VERSION 5.8 ;
BUSBITCHARS "[]" ;
DIVIDERCHAR "/" ;
UNITS
    DATABASE MICRONS 1000 ;
END UNITS

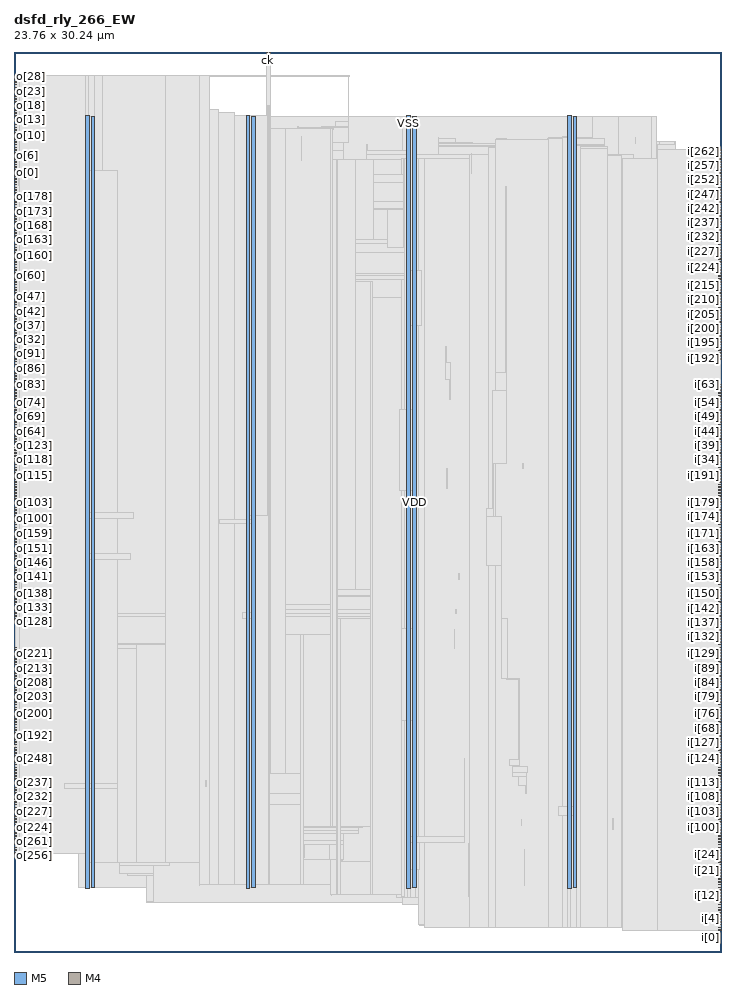
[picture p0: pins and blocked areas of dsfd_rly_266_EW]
MACRO dsfd_rly_266_EW
  FOREIGN dsfd_rly_266_EW 0 0 ;
  CLASS BLOCK ;
  SIZE 23.76 BY 30.24 ;
  PIN ck
    DIRECTION INPUT ;
    USE SIGNAL ;
    PORT
      LAYER M5 ;
        RECT  8.496 30.156 8.52 30.24 ;
    END
  END ck
  PIN i[0]
    DIRECTION INPUT ;
    USE SIGNAL ;
    PORT
      LAYER M4 ;
        RECT  23.676 0.72 23.76 0.744 ;
    END
  END i[0]
  PIN i[100]
    DIRECTION INPUT ;
    USE SIGNAL ;
    PORT
      LAYER M4 ;
        RECT  23.676 4.176 23.76 4.2 ;
    END
  END i[100]
  PIN i[101]
    DIRECTION INPUT ;
    USE SIGNAL ;
    PORT
      LAYER M4 ;
        RECT  23.676 4.272 23.76 4.296 ;
    END
  END i[101]
  PIN i[102]
    DIRECTION INPUT ;
    USE SIGNAL ;
    PORT
      LAYER M4 ;
        RECT  23.676 4.368 23.76 4.392 ;
    END
  END i[102]
  PIN i[103]
    DIRECTION INPUT ;
    USE SIGNAL ;
    PORT
      LAYER M4 ;
        RECT  23.676 4.464 23.76 4.488 ;
    END
  END i[103]
  PIN i[104]
    DIRECTION INPUT ;
    USE SIGNAL ;
    PORT
      LAYER M4 ;
        RECT  23.676 4.56 23.76 4.584 ;
    END
  END i[104]
  PIN i[105]
    DIRECTION INPUT ;
    USE SIGNAL ;
    PORT
      LAYER M4 ;
        RECT  23.676 4.656 23.76 4.68 ;
    END
  END i[105]
  PIN i[106]
    DIRECTION INPUT ;
    USE SIGNAL ;
    PORT
      LAYER M4 ;
        RECT  23.676 4.752 23.76 4.776 ;
    END
  END i[106]
  PIN i[107]
    DIRECTION INPUT ;
    USE SIGNAL ;
    PORT
      LAYER M4 ;
        RECT  23.676 4.848 23.76 4.872 ;
    END
  END i[107]
  PIN i[108]
    DIRECTION INPUT ;
    USE SIGNAL ;
    PORT
      LAYER M4 ;
        RECT  23.676 4.944 23.76 4.968 ;
    END
  END i[108]
  PIN i[109]
    DIRECTION INPUT ;
    USE SIGNAL ;
    PORT
      LAYER M4 ;
        RECT  23.676 5.04 23.76 5.064 ;
    END
  END i[109]
  PIN i[10]
    DIRECTION INPUT ;
    USE SIGNAL ;
    PORT
      LAYER M4 ;
        RECT  23.676 1.68 23.76 1.704 ;
    END
  END i[10]
  PIN i[110]
    DIRECTION INPUT ;
    USE SIGNAL ;
    PORT
      LAYER M4 ;
        RECT  23.676 5.136 23.76 5.16 ;
    END
  END i[110]
  PIN i[111]
    DIRECTION INPUT ;
    USE SIGNAL ;
    PORT
      LAYER M4 ;
        RECT  23.676 5.232 23.76 5.256 ;
    END
  END i[111]
  PIN i[112]
    DIRECTION INPUT ;
    USE SIGNAL ;
    PORT
      LAYER M4 ;
        RECT  23.676 5.328 23.76 5.352 ;
    END
  END i[112]
  PIN i[113]
    DIRECTION INPUT ;
    USE SIGNAL ;
    PORT
      LAYER M4 ;
        RECT  23.676 5.424 23.76 5.448 ;
    END
  END i[113]
  PIN i[114]
    DIRECTION INPUT ;
    USE SIGNAL ;
    PORT
      LAYER M4 ;
        RECT  23.676 5.52 23.76 5.544 ;
    END
  END i[114]
  PIN i[115]
    DIRECTION INPUT ;
    USE SIGNAL ;
    PORT
      LAYER M4 ;
        RECT  23.676 5.616 23.76 5.64 ;
    END
  END i[115]
  PIN i[116]
    DIRECTION INPUT ;
    USE SIGNAL ;
    PORT
      LAYER M4 ;
        RECT  23.676 5.712 23.76 5.736 ;
    END
  END i[116]
  PIN i[117]
    DIRECTION INPUT ;
    USE SIGNAL ;
    PORT
      LAYER M4 ;
        RECT  23.676 5.808 23.76 5.832 ;
    END
  END i[117]
  PIN i[118]
    DIRECTION INPUT ;
    USE SIGNAL ;
    PORT
      LAYER M4 ;
        RECT  23.676 5.904 23.76 5.928 ;
    END
  END i[118]
  PIN i[119]
    DIRECTION INPUT ;
    USE SIGNAL ;
    PORT
      LAYER M4 ;
        RECT  23.676 6 23.76 6.024 ;
    END
  END i[119]
  PIN i[11]
    DIRECTION INPUT ;
    USE SIGNAL ;
    PORT
      LAYER M4 ;
        RECT  23.676 1.776 23.76 1.8 ;
    END
  END i[11]
  PIN i[120]
    DIRECTION INPUT ;
    USE SIGNAL ;
    PORT
      LAYER M4 ;
        RECT  23.676 6.096 23.76 6.12 ;
    END
  END i[120]
  PIN i[121]
    DIRECTION INPUT ;
    USE SIGNAL ;
    PORT
      LAYER M4 ;
        RECT  23.676 6.192 23.76 6.216 ;
    END
  END i[121]
  PIN i[122]
    DIRECTION INPUT ;
    USE SIGNAL ;
    PORT
      LAYER M4 ;
        RECT  23.676 6.288 23.76 6.312 ;
    END
  END i[122]
  PIN i[123]
    DIRECTION INPUT ;
    USE SIGNAL ;
    PORT
      LAYER M4 ;
        RECT  23.676 6.384 23.76 6.408 ;
    END
  END i[123]
  PIN i[124]
    DIRECTION INPUT ;
    USE SIGNAL ;
    PORT
      LAYER M4 ;
        RECT  23.676 6.48 23.76 6.504 ;
    END
  END i[124]
  PIN i[125]
    DIRECTION INPUT ;
    USE SIGNAL ;
    PORT
      LAYER M4 ;
        RECT  23.676 6.576 23.76 6.6 ;
    END
  END i[125]
  PIN i[126]
    DIRECTION INPUT ;
    USE SIGNAL ;
    PORT
      LAYER M4 ;
        RECT  23.676 6.672 23.76 6.696 ;
    END
  END i[126]
  PIN i[127]
    DIRECTION INPUT ;
    USE SIGNAL ;
    PORT
      LAYER M4 ;
        RECT  23.676 6.768 23.76 6.792 ;
    END
  END i[127]
  PIN i[128]
    DIRECTION INPUT ;
    USE SIGNAL ;
    PORT
      LAYER M4 ;
        RECT  23.676 9.936 23.76 9.96 ;
    END
  END i[128]
  PIN i[129]
    DIRECTION INPUT ;
    USE SIGNAL ;
    PORT
      LAYER M4 ;
        RECT  23.676 10.032 23.76 10.056 ;
    END
  END i[129]
  PIN i[12]
    DIRECTION INPUT ;
    USE SIGNAL ;
    PORT
      LAYER M4 ;
        RECT  23.676 1.872 23.76 1.896 ;
    END
  END i[12]
  PIN i[130]
    DIRECTION INPUT ;
    USE SIGNAL ;
    PORT
      LAYER M4 ;
        RECT  23.676 10.128 23.76 10.152 ;
    END
  END i[130]
  PIN i[131]
    DIRECTION INPUT ;
    USE SIGNAL ;
    PORT
      LAYER M4 ;
        RECT  23.676 10.224 23.76 10.248 ;
    END
  END i[131]
  PIN i[132]
    DIRECTION INPUT ;
    USE SIGNAL ;
    PORT
      LAYER M4 ;
        RECT  23.676 10.32 23.76 10.344 ;
    END
  END i[132]
  PIN i[133]
    DIRECTION INPUT ;
    USE SIGNAL ;
    PORT
      LAYER M4 ;
        RECT  23.676 10.416 23.76 10.44 ;
    END
  END i[133]
  PIN i[134]
    DIRECTION INPUT ;
    USE SIGNAL ;
    PORT
      LAYER M4 ;
        RECT  23.676 10.512 23.76 10.536 ;
    END
  END i[134]
  PIN i[135]
    DIRECTION INPUT ;
    USE SIGNAL ;
    PORT
      LAYER M4 ;
        RECT  23.676 10.608 23.76 10.632 ;
    END
  END i[135]
  PIN i[136]
    DIRECTION INPUT ;
    USE SIGNAL ;
    PORT
      LAYER M4 ;
        RECT  23.676 10.704 23.76 10.728 ;
    END
  END i[136]
  PIN i[137]
    DIRECTION INPUT ;
    USE SIGNAL ;
    PORT
      LAYER M4 ;
        RECT  23.676 10.8 23.76 10.824 ;
    END
  END i[137]
  PIN i[138]
    DIRECTION INPUT ;
    USE SIGNAL ;
    PORT
      LAYER M4 ;
        RECT  23.676 10.896 23.76 10.92 ;
    END
  END i[138]
  PIN i[139]
    DIRECTION INPUT ;
    USE SIGNAL ;
    PORT
      LAYER M4 ;
        RECT  23.676 10.992 23.76 11.016 ;
    END
  END i[139]
  PIN i[13]
    DIRECTION INPUT ;
    USE SIGNAL ;
    PORT
      LAYER M4 ;
        RECT  23.676 1.968 23.76 1.992 ;
    END
  END i[13]
  PIN i[140]
    DIRECTION INPUT ;
    USE SIGNAL ;
    PORT
      LAYER M4 ;
        RECT  23.676 11.088 23.76 11.112 ;
    END
  END i[140]
  PIN i[141]
    DIRECTION INPUT ;
    USE SIGNAL ;
    PORT
      LAYER M4 ;
        RECT  23.676 11.184 23.76 11.208 ;
    END
  END i[141]
  PIN i[142]
    DIRECTION INPUT ;
    USE SIGNAL ;
    PORT
      LAYER M4 ;
        RECT  23.676 11.28 23.76 11.304 ;
    END
  END i[142]
  PIN i[143]
    DIRECTION INPUT ;
    USE SIGNAL ;
    PORT
      LAYER M4 ;
        RECT  23.676 11.376 23.76 11.4 ;
    END
  END i[143]
  PIN i[144]
    DIRECTION INPUT ;
    USE SIGNAL ;
    PORT
      LAYER M4 ;
        RECT  23.676 11.472 23.76 11.496 ;
    END
  END i[144]
  PIN i[145]
    DIRECTION INPUT ;
    USE SIGNAL ;
    PORT
      LAYER M4 ;
        RECT  23.676 11.568 23.76 11.592 ;
    END
  END i[145]
  PIN i[146]
    DIRECTION INPUT ;
    USE SIGNAL ;
    PORT
      LAYER M4 ;
        RECT  23.676 11.664 23.76 11.688 ;
    END
  END i[146]
  PIN i[147]
    DIRECTION INPUT ;
    USE SIGNAL ;
    PORT
      LAYER M4 ;
        RECT  23.676 11.76 23.76 11.784 ;
    END
  END i[147]
  PIN i[148]
    DIRECTION INPUT ;
    USE SIGNAL ;
    PORT
      LAYER M4 ;
        RECT  23.676 11.856 23.76 11.88 ;
    END
  END i[148]
  PIN i[149]
    DIRECTION INPUT ;
    USE SIGNAL ;
    PORT
      LAYER M4 ;
        RECT  23.676 11.952 23.76 11.976 ;
    END
  END i[149]
  PIN i[14]
    DIRECTION INPUT ;
    USE SIGNAL ;
    PORT
      LAYER M4 ;
        RECT  23.676 2.064 23.76 2.088 ;
    END
  END i[14]
  PIN i[150]
    DIRECTION INPUT ;
    USE SIGNAL ;
    PORT
      LAYER M4 ;
        RECT  23.676 12.048 23.76 12.072 ;
    END
  END i[150]
  PIN i[151]
    DIRECTION INPUT ;
    USE SIGNAL ;
    PORT
      LAYER M4 ;
        RECT  23.676 12.144 23.76 12.168 ;
    END
  END i[151]
  PIN i[152]
    DIRECTION INPUT ;
    USE SIGNAL ;
    PORT
      LAYER M4 ;
        RECT  23.676 12.24 23.76 12.264 ;
    END
  END i[152]
  PIN i[153]
    DIRECTION INPUT ;
    USE SIGNAL ;
    PORT
      LAYER M4 ;
        RECT  23.676 12.336 23.76 12.36 ;
    END
  END i[153]
  PIN i[154]
    DIRECTION INPUT ;
    USE SIGNAL ;
    PORT
      LAYER M4 ;
        RECT  23.676 12.432 23.76 12.456 ;
    END
  END i[154]
  PIN i[155]
    DIRECTION INPUT ;
    USE SIGNAL ;
    PORT
      LAYER M4 ;
        RECT  23.676 12.528 23.76 12.552 ;
    END
  END i[155]
  PIN i[156]
    DIRECTION INPUT ;
    USE SIGNAL ;
    PORT
      LAYER M4 ;
        RECT  23.676 12.624 23.76 12.648 ;
    END
  END i[156]
  PIN i[157]
    DIRECTION INPUT ;
    USE SIGNAL ;
    PORT
      LAYER M4 ;
        RECT  23.676 12.72 23.76 12.744 ;
    END
  END i[157]
  PIN i[158]
    DIRECTION INPUT ;
    USE SIGNAL ;
    PORT
      LAYER M4 ;
        RECT  23.676 12.816 23.76 12.84 ;
    END
  END i[158]
  PIN i[159]
    DIRECTION INPUT ;
    USE SIGNAL ;
    PORT
      LAYER M4 ;
        RECT  23.676 12.912 23.76 12.936 ;
    END
  END i[159]
  PIN i[15]
    DIRECTION INPUT ;
    USE SIGNAL ;
    PORT
      LAYER M4 ;
        RECT  23.676 2.16 23.76 2.184 ;
    END
  END i[15]
  PIN i[160]
    DIRECTION INPUT ;
    USE SIGNAL ;
    PORT
      LAYER M4 ;
        RECT  23.676 13.008 23.76 13.032 ;
    END
  END i[160]
  PIN i[161]
    DIRECTION INPUT ;
    USE SIGNAL ;
    PORT
      LAYER M4 ;
        RECT  23.676 13.104 23.76 13.128 ;
    END
  END i[161]
  PIN i[162]
    DIRECTION INPUT ;
    USE SIGNAL ;
    PORT
      LAYER M4 ;
        RECT  23.676 13.2 23.76 13.224 ;
    END
  END i[162]
  PIN i[163]
    DIRECTION INPUT ;
    USE SIGNAL ;
    PORT
      LAYER M4 ;
        RECT  23.676 13.296 23.76 13.32 ;
    END
  END i[163]
  PIN i[164]
    DIRECTION INPUT ;
    USE SIGNAL ;
    PORT
      LAYER M4 ;
        RECT  23.676 13.392 23.76 13.416 ;
    END
  END i[164]
  PIN i[165]
    DIRECTION INPUT ;
    USE SIGNAL ;
    PORT
      LAYER M4 ;
        RECT  23.676 13.488 23.76 13.512 ;
    END
  END i[165]
  PIN i[166]
    DIRECTION INPUT ;
    USE SIGNAL ;
    PORT
      LAYER M4 ;
        RECT  23.676 13.584 23.76 13.608 ;
    END
  END i[166]
  PIN i[167]
    DIRECTION INPUT ;
    USE SIGNAL ;
    PORT
      LAYER M4 ;
        RECT  23.676 13.68 23.76 13.704 ;
    END
  END i[167]
  PIN i[168]
    DIRECTION INPUT ;
    USE SIGNAL ;
    PORT
      LAYER M4 ;
        RECT  23.676 13.776 23.76 13.8 ;
    END
  END i[168]
  PIN i[169]
    DIRECTION INPUT ;
    USE SIGNAL ;
    PORT
      LAYER M4 ;
        RECT  23.676 13.872 23.76 13.896 ;
    END
  END i[169]
  PIN i[16]
    DIRECTION INPUT ;
    USE SIGNAL ;
    PORT
      LAYER M4 ;
        RECT  23.676 2.256 23.76 2.28 ;
    END
  END i[16]
  PIN i[170]
    DIRECTION INPUT ;
    USE SIGNAL ;
    PORT
      LAYER M4 ;
        RECT  23.676 13.968 23.76 13.992 ;
    END
  END i[170]
  PIN i[171]
    DIRECTION INPUT ;
    USE SIGNAL ;
    PORT
      LAYER M4 ;
        RECT  23.676 14.064 23.76 14.088 ;
    END
  END i[171]
  PIN i[172]
    DIRECTION INPUT ;
    USE SIGNAL ;
    PORT
      LAYER M4 ;
        RECT  23.676 14.16 23.76 14.184 ;
    END
  END i[172]
  PIN i[173]
    DIRECTION INPUT ;
    USE SIGNAL ;
    PORT
      LAYER M4 ;
        RECT  23.676 14.256 23.76 14.28 ;
    END
  END i[173]
  PIN i[174]
    DIRECTION INPUT ;
    USE SIGNAL ;
    PORT
      LAYER M4 ;
        RECT  23.676 14.352 23.76 14.376 ;
    END
  END i[174]
  PIN i[175]
    DIRECTION INPUT ;
    USE SIGNAL ;
    PORT
      LAYER M4 ;
        RECT  23.676 14.448 23.76 14.472 ;
    END
  END i[175]
  PIN i[176]
    DIRECTION INPUT ;
    USE SIGNAL ;
    PORT
      LAYER M4 ;
        RECT  23.676 14.544 23.76 14.568 ;
    END
  END i[176]
  PIN i[177]
    DIRECTION INPUT ;
    USE SIGNAL ;
    PORT
      LAYER M4 ;
        RECT  23.676 14.64 23.76 14.664 ;
    END
  END i[177]
  PIN i[178]
    DIRECTION INPUT ;
    USE SIGNAL ;
    PORT
      LAYER M4 ;
        RECT  23.676 14.736 23.76 14.76 ;
    END
  END i[178]
  PIN i[179]
    DIRECTION INPUT ;
    USE SIGNAL ;
    PORT
      LAYER M4 ;
        RECT  23.676 14.832 23.76 14.856 ;
    END
  END i[179]
  PIN i[17]
    DIRECTION INPUT ;
    USE SIGNAL ;
    PORT
      LAYER M4 ;
        RECT  23.676 2.352 23.76 2.376 ;
    END
  END i[17]
  PIN i[180]
    DIRECTION INPUT ;
    USE SIGNAL ;
    PORT
      LAYER M4 ;
        RECT  23.676 14.928 23.76 14.952 ;
    END
  END i[180]
  PIN i[181]
    DIRECTION INPUT ;
    USE SIGNAL ;
    PORT
      LAYER M4 ;
        RECT  23.676 15.024 23.76 15.048 ;
    END
  END i[181]
  PIN i[182]
    DIRECTION INPUT ;
    USE SIGNAL ;
    PORT
      LAYER M4 ;
        RECT  23.676 15.12 23.76 15.144 ;
    END
  END i[182]
  PIN i[183]
    DIRECTION INPUT ;
    USE SIGNAL ;
    PORT
      LAYER M4 ;
        RECT  23.676 15.216 23.76 15.24 ;
    END
  END i[183]
  PIN i[184]
    DIRECTION INPUT ;
    USE SIGNAL ;
    PORT
      LAYER M4 ;
        RECT  23.676 15.312 23.76 15.336 ;
    END
  END i[184]
  PIN i[185]
    DIRECTION INPUT ;
    USE SIGNAL ;
    PORT
      LAYER M4 ;
        RECT  23.676 15.408 23.76 15.432 ;
    END
  END i[185]
  PIN i[186]
    DIRECTION INPUT ;
    USE SIGNAL ;
    PORT
      LAYER M4 ;
        RECT  23.676 15.504 23.76 15.528 ;
    END
  END i[186]
  PIN i[187]
    DIRECTION INPUT ;
    USE SIGNAL ;
    PORT
      LAYER M4 ;
        RECT  23.676 15.6 23.76 15.624 ;
    END
  END i[187]
  PIN i[188]
    DIRECTION INPUT ;
    USE SIGNAL ;
    PORT
      LAYER M4 ;
        RECT  23.676 15.696 23.76 15.72 ;
    END
  END i[188]
  PIN i[189]
    DIRECTION INPUT ;
    USE SIGNAL ;
    PORT
      LAYER M4 ;
        RECT  23.676 15.792 23.76 15.816 ;
    END
  END i[189]
  PIN i[18]
    DIRECTION INPUT ;
    USE SIGNAL ;
    PORT
      LAYER M4 ;
        RECT  23.676 2.448 23.76 2.472 ;
    END
  END i[18]
  PIN i[190]
    DIRECTION INPUT ;
    USE SIGNAL ;
    PORT
      LAYER M4 ;
        RECT  23.676 15.888 23.76 15.912 ;
    END
  END i[190]
  PIN i[191]
    DIRECTION INPUT ;
    USE SIGNAL ;
    PORT
      LAYER M4 ;
        RECT  23.676 15.984 23.76 16.008 ;
    END
  END i[191]
  PIN i[192]
    DIRECTION INPUT ;
    USE SIGNAL ;
    PORT
      LAYER M4 ;
        RECT  23.676 19.92 23.76 19.944 ;
    END
  END i[192]
  PIN i[193]
    DIRECTION INPUT ;
    USE SIGNAL ;
    PORT
      LAYER M4 ;
        RECT  23.676 20.016 23.76 20.04 ;
    END
  END i[193]
  PIN i[194]
    DIRECTION INPUT ;
    USE SIGNAL ;
    PORT
      LAYER M4 ;
        RECT  23.676 20.112 23.76 20.136 ;
    END
  END i[194]
  PIN i[195]
    DIRECTION INPUT ;
    USE SIGNAL ;
    PORT
      LAYER M4 ;
        RECT  23.676 20.208 23.76 20.232 ;
    END
  END i[195]
  PIN i[196]
    DIRECTION INPUT ;
    USE SIGNAL ;
    PORT
      LAYER M4 ;
        RECT  23.676 20.304 23.76 20.328 ;
    END
  END i[196]
  PIN i[197]
    DIRECTION INPUT ;
    USE SIGNAL ;
    PORT
      LAYER M4 ;
        RECT  23.676 20.4 23.76 20.424 ;
    END
  END i[197]
  PIN i[198]
    DIRECTION INPUT ;
    USE SIGNAL ;
    PORT
      LAYER M4 ;
        RECT  23.676 20.496 23.76 20.52 ;
    END
  END i[198]
  PIN i[199]
    DIRECTION INPUT ;
    USE SIGNAL ;
    PORT
      LAYER M4 ;
        RECT  23.676 20.592 23.76 20.616 ;
    END
  END i[199]
  PIN i[19]
    DIRECTION INPUT ;
    USE SIGNAL ;
    PORT
      LAYER M4 ;
        RECT  23.676 2.544 23.76 2.568 ;
    END
  END i[19]
  PIN i[1]
    DIRECTION INPUT ;
    USE SIGNAL ;
    PORT
      LAYER M4 ;
        RECT  23.676 0.816 23.76 0.84 ;
    END
  END i[1]
  PIN i[200]
    DIRECTION INPUT ;
    USE SIGNAL ;
    PORT
      LAYER M4 ;
        RECT  23.676 20.688 23.76 20.712 ;
    END
  END i[200]
  PIN i[201]
    DIRECTION INPUT ;
    USE SIGNAL ;
    PORT
      LAYER M4 ;
        RECT  23.676 20.784 23.76 20.808 ;
    END
  END i[201]
  PIN i[202]
    DIRECTION INPUT ;
    USE SIGNAL ;
    PORT
      LAYER M4 ;
        RECT  23.676 20.88 23.76 20.904 ;
    END
  END i[202]
  PIN i[203]
    DIRECTION INPUT ;
    USE SIGNAL ;
    PORT
      LAYER M4 ;
        RECT  23.676 20.976 23.76 21 ;
    END
  END i[203]
  PIN i[204]
    DIRECTION INPUT ;
    USE SIGNAL ;
    PORT
      LAYER M4 ;
        RECT  23.676 21.072 23.76 21.096 ;
    END
  END i[204]
  PIN i[205]
    DIRECTION INPUT ;
    USE SIGNAL ;
    PORT
      LAYER M4 ;
        RECT  23.676 21.168 23.76 21.192 ;
    END
  END i[205]
  PIN i[206]
    DIRECTION INPUT ;
    USE SIGNAL ;
    PORT
      LAYER M4 ;
        RECT  23.676 21.264 23.76 21.288 ;
    END
  END i[206]
  PIN i[207]
    DIRECTION INPUT ;
    USE SIGNAL ;
    PORT
      LAYER M4 ;
        RECT  23.676 21.36 23.76 21.384 ;
    END
  END i[207]
  PIN i[208]
    DIRECTION INPUT ;
    USE SIGNAL ;
    PORT
      LAYER M4 ;
        RECT  23.676 21.456 23.76 21.48 ;
    END
  END i[208]
  PIN i[209]
    DIRECTION INPUT ;
    USE SIGNAL ;
    PORT
      LAYER M4 ;
        RECT  23.676 21.552 23.76 21.576 ;
    END
  END i[209]
  PIN i[20]
    DIRECTION INPUT ;
    USE SIGNAL ;
    PORT
      LAYER M4 ;
        RECT  23.676 2.64 23.76 2.664 ;
    END
  END i[20]
  PIN i[210]
    DIRECTION INPUT ;
    USE SIGNAL ;
    PORT
      LAYER M4 ;
        RECT  23.676 21.648 23.76 21.672 ;
    END
  END i[210]
  PIN i[211]
    DIRECTION INPUT ;
    USE SIGNAL ;
    PORT
      LAYER M4 ;
        RECT  23.676 21.744 23.76 21.768 ;
    END
  END i[211]
  PIN i[212]
    DIRECTION INPUT ;
    USE SIGNAL ;
    PORT
      LAYER M4 ;
        RECT  23.676 21.84 23.76 21.864 ;
    END
  END i[212]
  PIN i[213]
    DIRECTION INPUT ;
    USE SIGNAL ;
    PORT
      LAYER M4 ;
        RECT  23.676 21.936 23.76 21.96 ;
    END
  END i[213]
  PIN i[214]
    DIRECTION INPUT ;
    USE SIGNAL ;
    PORT
      LAYER M4 ;
        RECT  23.676 22.032 23.76 22.056 ;
    END
  END i[214]
  PIN i[215]
    DIRECTION INPUT ;
    USE SIGNAL ;
    PORT
      LAYER M4 ;
        RECT  23.676 22.128 23.76 22.152 ;
    END
  END i[215]
  PIN i[216]
    DIRECTION INPUT ;
    USE SIGNAL ;
    PORT
      LAYER M4 ;
        RECT  23.676 22.224 23.76 22.248 ;
    END
  END i[216]
  PIN i[217]
    DIRECTION INPUT ;
    USE SIGNAL ;
    PORT
      LAYER M4 ;
        RECT  23.676 22.32 23.76 22.344 ;
    END
  END i[217]
  PIN i[218]
    DIRECTION INPUT ;
    USE SIGNAL ;
    PORT
      LAYER M4 ;
        RECT  23.676 22.416 23.76 22.44 ;
    END
  END i[218]
  PIN i[219]
    DIRECTION INPUT ;
    USE SIGNAL ;
    PORT
      LAYER M4 ;
        RECT  23.676 22.512 23.76 22.536 ;
    END
  END i[219]
  PIN i[21]
    DIRECTION INPUT ;
    USE SIGNAL ;
    PORT
      LAYER M4 ;
        RECT  23.676 2.736 23.76 2.76 ;
    END
  END i[21]
  PIN i[220]
    DIRECTION INPUT ;
    USE SIGNAL ;
    PORT
      LAYER M4 ;
        RECT  23.676 22.608 23.76 22.632 ;
    END
  END i[220]
  PIN i[221]
    DIRECTION INPUT ;
    USE SIGNAL ;
    PORT
      LAYER M4 ;
        RECT  23.676 22.704 23.76 22.728 ;
    END
  END i[221]
  PIN i[222]
    DIRECTION INPUT ;
    USE SIGNAL ;
    PORT
      LAYER M4 ;
        RECT  23.676 22.8 23.76 22.824 ;
    END
  END i[222]
  PIN i[223]
    DIRECTION INPUT ;
    USE SIGNAL ;
    PORT
      LAYER M4 ;
        RECT  23.676 22.896 23.76 22.92 ;
    END
  END i[223]
  PIN i[224]
    DIRECTION INPUT ;
    USE SIGNAL ;
    PORT
      LAYER M4 ;
        RECT  23.676 22.992 23.76 23.016 ;
    END
  END i[224]
  PIN i[225]
    DIRECTION INPUT ;
    USE SIGNAL ;
    PORT
      LAYER M4 ;
        RECT  23.676 23.088 23.76 23.112 ;
    END
  END i[225]
  PIN i[226]
    DIRECTION INPUT ;
    USE SIGNAL ;
    PORT
      LAYER M4 ;
        RECT  23.676 23.184 23.76 23.208 ;
    END
  END i[226]
  PIN i[227]
    DIRECTION INPUT ;
    USE SIGNAL ;
    PORT
      LAYER M4 ;
        RECT  23.676 23.28 23.76 23.304 ;
    END
  END i[227]
  PIN i[228]
    DIRECTION INPUT ;
    USE SIGNAL ;
    PORT
      LAYER M4 ;
        RECT  23.676 23.376 23.76 23.4 ;
    END
  END i[228]
  PIN i[229]
    DIRECTION INPUT ;
    USE SIGNAL ;
    PORT
      LAYER M4 ;
        RECT  23.676 23.472 23.76 23.496 ;
    END
  END i[229]
  PIN i[22]
    DIRECTION INPUT ;
    USE SIGNAL ;
    PORT
      LAYER M4 ;
        RECT  23.676 2.832 23.76 2.856 ;
    END
  END i[22]
  PIN i[230]
    DIRECTION INPUT ;
    USE SIGNAL ;
    PORT
      LAYER M4 ;
        RECT  23.676 23.568 23.76 23.592 ;
    END
  END i[230]
  PIN i[231]
    DIRECTION INPUT ;
    USE SIGNAL ;
    PORT
      LAYER M4 ;
        RECT  23.676 23.664 23.76 23.688 ;
    END
  END i[231]
  PIN i[232]
    DIRECTION INPUT ;
    USE SIGNAL ;
    PORT
      LAYER M4 ;
        RECT  23.676 23.76 23.76 23.784 ;
    END
  END i[232]
  PIN i[233]
    DIRECTION INPUT ;
    USE SIGNAL ;
    PORT
      LAYER M4 ;
        RECT  23.676 23.856 23.76 23.88 ;
    END
  END i[233]
  PIN i[234]
    DIRECTION INPUT ;
    USE SIGNAL ;
    PORT
      LAYER M4 ;
        RECT  23.676 23.952 23.76 23.976 ;
    END
  END i[234]
  PIN i[235]
    DIRECTION INPUT ;
    USE SIGNAL ;
    PORT
      LAYER M4 ;
        RECT  23.676 24.048 23.76 24.072 ;
    END
  END i[235]
  PIN i[236]
    DIRECTION INPUT ;
    USE SIGNAL ;
    PORT
      LAYER M4 ;
        RECT  23.676 24.144 23.76 24.168 ;
    END
  END i[236]
  PIN i[237]
    DIRECTION INPUT ;
    USE SIGNAL ;
    PORT
      LAYER M4 ;
        RECT  23.676 24.24 23.76 24.264 ;
    END
  END i[237]
  PIN i[238]
    DIRECTION INPUT ;
    USE SIGNAL ;
    PORT
      LAYER M4 ;
        RECT  23.676 24.336 23.76 24.36 ;
    END
  END i[238]
  PIN i[239]
    DIRECTION INPUT ;
    USE SIGNAL ;
    PORT
      LAYER M4 ;
        RECT  23.676 24.432 23.76 24.456 ;
    END
  END i[239]
  PIN i[23]
    DIRECTION INPUT ;
    USE SIGNAL ;
    PORT
      LAYER M4 ;
        RECT  23.676 2.928 23.76 2.952 ;
    END
  END i[23]
  PIN i[240]
    DIRECTION INPUT ;
    USE SIGNAL ;
    PORT
      LAYER M4 ;
        RECT  23.676 24.528 23.76 24.552 ;
    END
  END i[240]
  PIN i[241]
    DIRECTION INPUT ;
    USE SIGNAL ;
    PORT
      LAYER M4 ;
        RECT  23.676 24.624 23.76 24.648 ;
    END
  END i[241]
  PIN i[242]
    DIRECTION INPUT ;
    USE SIGNAL ;
    PORT
      LAYER M4 ;
        RECT  23.676 24.72 23.76 24.744 ;
    END
  END i[242]
  PIN i[243]
    DIRECTION INPUT ;
    USE SIGNAL ;
    PORT
      LAYER M4 ;
        RECT  23.676 24.816 23.76 24.84 ;
    END
  END i[243]
  PIN i[244]
    DIRECTION INPUT ;
    USE SIGNAL ;
    PORT
      LAYER M4 ;
        RECT  23.676 24.912 23.76 24.936 ;
    END
  END i[244]
  PIN i[245]
    DIRECTION INPUT ;
    USE SIGNAL ;
    PORT
      LAYER M4 ;
        RECT  23.676 25.008 23.76 25.032 ;
    END
  END i[245]
  PIN i[246]
    DIRECTION INPUT ;
    USE SIGNAL ;
    PORT
      LAYER M4 ;
        RECT  23.676 25.104 23.76 25.128 ;
    END
  END i[246]
  PIN i[247]
    DIRECTION INPUT ;
    USE SIGNAL ;
    PORT
      LAYER M4 ;
        RECT  23.676 25.2 23.76 25.224 ;
    END
  END i[247]
  PIN i[248]
    DIRECTION INPUT ;
    USE SIGNAL ;
    PORT
      LAYER M4 ;
        RECT  23.676 25.296 23.76 25.32 ;
    END
  END i[248]
  PIN i[249]
    DIRECTION INPUT ;
    USE SIGNAL ;
    PORT
      LAYER M4 ;
        RECT  23.676 25.392 23.76 25.416 ;
    END
  END i[249]
  PIN i[24]
    DIRECTION INPUT ;
    USE SIGNAL ;
    PORT
      LAYER M4 ;
        RECT  23.676 3.024 23.76 3.048 ;
    END
  END i[24]
  PIN i[250]
    DIRECTION INPUT ;
    USE SIGNAL ;
    PORT
      LAYER M4 ;
        RECT  23.676 25.488 23.76 25.512 ;
    END
  END i[250]
  PIN i[251]
    DIRECTION INPUT ;
    USE SIGNAL ;
    PORT
      LAYER M4 ;
        RECT  23.676 25.584 23.76 25.608 ;
    END
  END i[251]
  PIN i[252]
    DIRECTION INPUT ;
    USE SIGNAL ;
    PORT
      LAYER M4 ;
        RECT  23.676 25.68 23.76 25.704 ;
    END
  END i[252]
  PIN i[253]
    DIRECTION INPUT ;
    USE SIGNAL ;
    PORT
      LAYER M4 ;
        RECT  23.676 25.776 23.76 25.8 ;
    END
  END i[253]
  PIN i[254]
    DIRECTION INPUT ;
    USE SIGNAL ;
    PORT
      LAYER M4 ;
        RECT  23.676 25.872 23.76 25.896 ;
    END
  END i[254]
  PIN i[255]
    DIRECTION INPUT ;
    USE SIGNAL ;
    PORT
      LAYER M4 ;
        RECT  23.676 25.968 23.76 25.992 ;
    END
  END i[255]
  PIN i[256]
    DIRECTION INPUT ;
    USE SIGNAL ;
    PORT
      LAYER M4 ;
        RECT  23.676 26.064 23.76 26.088 ;
    END
  END i[256]
  PIN i[257]
    DIRECTION INPUT ;
    USE SIGNAL ;
    PORT
      LAYER M4 ;
        RECT  23.676 26.16 23.76 26.184 ;
    END
  END i[257]
  PIN i[258]
    DIRECTION INPUT ;
    USE SIGNAL ;
    PORT
      LAYER M4 ;
        RECT  23.676 26.256 23.76 26.28 ;
    END
  END i[258]
  PIN i[259]
    DIRECTION INPUT ;
    USE SIGNAL ;
    PORT
      LAYER M4 ;
        RECT  23.676 26.352 23.76 26.376 ;
    END
  END i[259]
  PIN i[25]
    DIRECTION INPUT ;
    USE SIGNAL ;
    PORT
      LAYER M4 ;
        RECT  23.676 3.12 23.76 3.144 ;
    END
  END i[25]
  PIN i[260]
    DIRECTION INPUT ;
    USE SIGNAL ;
    PORT
      LAYER M4 ;
        RECT  23.676 26.448 23.76 26.472 ;
    END
  END i[260]
  PIN i[261]
    DIRECTION INPUT ;
    USE SIGNAL ;
    PORT
      LAYER M4 ;
        RECT  23.676 26.544 23.76 26.568 ;
    END
  END i[261]
  PIN i[262]
    DIRECTION INPUT ;
    USE SIGNAL ;
    PORT
      LAYER M4 ;
        RECT  23.676 26.64 23.76 26.664 ;
    END
  END i[262]
  PIN i[263]
    DIRECTION INPUT ;
    USE SIGNAL ;
    PORT
      LAYER M4 ;
        RECT  23.676 26.736 23.76 26.76 ;
    END
  END i[263]
  PIN i[264]
    DIRECTION INPUT ;
    USE SIGNAL ;
    PORT
      LAYER M4 ;
        RECT  23.676 26.832 23.76 26.856 ;
    END
  END i[264]
  PIN i[265]
    DIRECTION INPUT ;
    USE SIGNAL ;
    PORT
      LAYER M4 ;
        RECT  23.676 26.928 23.76 26.952 ;
    END
  END i[265]
  PIN i[26]
    DIRECTION INPUT ;
    USE SIGNAL ;
    PORT
      LAYER M4 ;
        RECT  23.676 3.216 23.76 3.24 ;
    END
  END i[26]
  PIN i[27]
    DIRECTION INPUT ;
    USE SIGNAL ;
    PORT
      LAYER M4 ;
        RECT  23.676 3.312 23.76 3.336 ;
    END
  END i[27]
  PIN i[28]
    DIRECTION INPUT ;
    USE SIGNAL ;
    PORT
      LAYER M4 ;
        RECT  23.676 3.408 23.76 3.432 ;
    END
  END i[28]
  PIN i[29]
    DIRECTION INPUT ;
    USE SIGNAL ;
    PORT
      LAYER M4 ;
        RECT  23.676 3.504 23.76 3.528 ;
    END
  END i[29]
  PIN i[2]
    DIRECTION INPUT ;
    USE SIGNAL ;
    PORT
      LAYER M4 ;
        RECT  23.676 0.912 23.76 0.936 ;
    END
  END i[2]
  PIN i[30]
    DIRECTION INPUT ;
    USE SIGNAL ;
    PORT
      LAYER M4 ;
        RECT  23.676 3.6 23.76 3.624 ;
    END
  END i[30]
  PIN i[31]
    DIRECTION INPUT ;
    USE SIGNAL ;
    PORT
      LAYER M4 ;
        RECT  23.676 3.696 23.76 3.72 ;
    END
  END i[31]
  PIN i[32]
    DIRECTION INPUT ;
    USE SIGNAL ;
    PORT
      LAYER M4 ;
        RECT  23.676 16.08 23.76 16.104 ;
    END
  END i[32]
  PIN i[33]
    DIRECTION INPUT ;
    USE SIGNAL ;
    PORT
      LAYER M4 ;
        RECT  23.676 16.176 23.76 16.2 ;
    END
  END i[33]
  PIN i[34]
    DIRECTION INPUT ;
    USE SIGNAL ;
    PORT
      LAYER M4 ;
        RECT  23.676 16.272 23.76 16.296 ;
    END
  END i[34]
  PIN i[35]
    DIRECTION INPUT ;
    USE SIGNAL ;
    PORT
      LAYER M4 ;
        RECT  23.676 16.368 23.76 16.392 ;
    END
  END i[35]
  PIN i[36]
    DIRECTION INPUT ;
    USE SIGNAL ;
    PORT
      LAYER M4 ;
        RECT  23.676 16.464 23.76 16.488 ;
    END
  END i[36]
  PIN i[37]
    DIRECTION INPUT ;
    USE SIGNAL ;
    PORT
      LAYER M4 ;
        RECT  23.676 16.56 23.76 16.584 ;
    END
  END i[37]
  PIN i[38]
    DIRECTION INPUT ;
    USE SIGNAL ;
    PORT
      LAYER M4 ;
        RECT  23.676 16.656 23.76 16.68 ;
    END
  END i[38]
  PIN i[39]
    DIRECTION INPUT ;
    USE SIGNAL ;
    PORT
      LAYER M4 ;
        RECT  23.676 16.752 23.76 16.776 ;
    END
  END i[39]
  PIN i[3]
    DIRECTION INPUT ;
    USE SIGNAL ;
    PORT
      LAYER M4 ;
        RECT  23.676 1.008 23.76 1.032 ;
    END
  END i[3]
  PIN i[40]
    DIRECTION INPUT ;
    USE SIGNAL ;
    PORT
      LAYER M4 ;
        RECT  23.676 16.848 23.76 16.872 ;
    END
  END i[40]
  PIN i[41]
    DIRECTION INPUT ;
    USE SIGNAL ;
    PORT
      LAYER M4 ;
        RECT  23.676 16.944 23.76 16.968 ;
    END
  END i[41]
  PIN i[42]
    DIRECTION INPUT ;
    USE SIGNAL ;
    PORT
      LAYER M4 ;
        RECT  23.676 17.04 23.76 17.064 ;
    END
  END i[42]
  PIN i[43]
    DIRECTION INPUT ;
    USE SIGNAL ;
    PORT
      LAYER M4 ;
        RECT  23.676 17.136 23.76 17.16 ;
    END
  END i[43]
  PIN i[44]
    DIRECTION INPUT ;
    USE SIGNAL ;
    PORT
      LAYER M4 ;
        RECT  23.676 17.232 23.76 17.256 ;
    END
  END i[44]
  PIN i[45]
    DIRECTION INPUT ;
    USE SIGNAL ;
    PORT
      LAYER M4 ;
        RECT  23.676 17.328 23.76 17.352 ;
    END
  END i[45]
  PIN i[46]
    DIRECTION INPUT ;
    USE SIGNAL ;
    PORT
      LAYER M4 ;
        RECT  23.676 17.424 23.76 17.448 ;
    END
  END i[46]
  PIN i[47]
    DIRECTION INPUT ;
    USE SIGNAL ;
    PORT
      LAYER M4 ;
        RECT  23.676 17.52 23.76 17.544 ;
    END
  END i[47]
  PIN i[48]
    DIRECTION INPUT ;
    USE SIGNAL ;
    PORT
      LAYER M4 ;
        RECT  23.676 17.616 23.76 17.64 ;
    END
  END i[48]
  PIN i[49]
    DIRECTION INPUT ;
    USE SIGNAL ;
    PORT
      LAYER M4 ;
        RECT  23.676 17.712 23.76 17.736 ;
    END
  END i[49]
  PIN i[4]
    DIRECTION INPUT ;
    USE SIGNAL ;
    PORT
      LAYER M4 ;
        RECT  23.676 1.104 23.76 1.128 ;
    END
  END i[4]
  PIN i[50]
    DIRECTION INPUT ;
    USE SIGNAL ;
    PORT
      LAYER M4 ;
        RECT  23.676 17.808 23.76 17.832 ;
    END
  END i[50]
  PIN i[51]
    DIRECTION INPUT ;
    USE SIGNAL ;
    PORT
      LAYER M4 ;
        RECT  23.676 17.904 23.76 17.928 ;
    END
  END i[51]
  PIN i[52]
    DIRECTION INPUT ;
    USE SIGNAL ;
    PORT
      LAYER M4 ;
        RECT  23.676 18 23.76 18.024 ;
    END
  END i[52]
  PIN i[53]
    DIRECTION INPUT ;
    USE SIGNAL ;
    PORT
      LAYER M4 ;
        RECT  23.676 18.096 23.76 18.12 ;
    END
  END i[53]
  PIN i[54]
    DIRECTION INPUT ;
    USE SIGNAL ;
    PORT
      LAYER M4 ;
        RECT  23.676 18.192 23.76 18.216 ;
    END
  END i[54]
  PIN i[55]
    DIRECTION INPUT ;
    USE SIGNAL ;
    PORT
      LAYER M4 ;
        RECT  23.676 18.288 23.76 18.312 ;
    END
  END i[55]
  PIN i[56]
    DIRECTION INPUT ;
    USE SIGNAL ;
    PORT
      LAYER M4 ;
        RECT  23.676 18.384 23.76 18.408 ;
    END
  END i[56]
  PIN i[57]
    DIRECTION INPUT ;
    USE SIGNAL ;
    PORT
      LAYER M4 ;
        RECT  23.676 18.48 23.76 18.504 ;
    END
  END i[57]
  PIN i[58]
    DIRECTION INPUT ;
    USE SIGNAL ;
    PORT
      LAYER M4 ;
        RECT  23.676 18.576 23.76 18.6 ;
    END
  END i[58]
  PIN i[59]
    DIRECTION INPUT ;
    USE SIGNAL ;
    PORT
      LAYER M4 ;
        RECT  23.676 18.672 23.76 18.696 ;
    END
  END i[59]
  PIN i[5]
    DIRECTION INPUT ;
    USE SIGNAL ;
    PORT
      LAYER M4 ;
        RECT  23.676 1.2 23.76 1.224 ;
    END
  END i[5]
  PIN i[60]
    DIRECTION INPUT ;
    USE SIGNAL ;
    PORT
      LAYER M4 ;
        RECT  23.676 18.768 23.76 18.792 ;
    END
  END i[60]
  PIN i[61]
    DIRECTION INPUT ;
    USE SIGNAL ;
    PORT
      LAYER M4 ;
        RECT  23.676 18.864 23.76 18.888 ;
    END
  END i[61]
  PIN i[62]
    DIRECTION INPUT ;
    USE SIGNAL ;
    PORT
      LAYER M4 ;
        RECT  23.676 18.96 23.76 18.984 ;
    END
  END i[62]
  PIN i[63]
    DIRECTION INPUT ;
    USE SIGNAL ;
    PORT
      LAYER M4 ;
        RECT  23.676 19.056 23.76 19.08 ;
    END
  END i[63]
  PIN i[64]
    DIRECTION INPUT ;
    USE SIGNAL ;
    PORT
      LAYER M4 ;
        RECT  23.676 6.864 23.76 6.888 ;
    END
  END i[64]
  PIN i[65]
    DIRECTION INPUT ;
    USE SIGNAL ;
    PORT
      LAYER M4 ;
        RECT  23.676 6.96 23.76 6.984 ;
    END
  END i[65]
  PIN i[66]
    DIRECTION INPUT ;
    USE SIGNAL ;
    PORT
      LAYER M4 ;
        RECT  23.676 7.056 23.76 7.08 ;
    END
  END i[66]
  PIN i[67]
    DIRECTION INPUT ;
    USE SIGNAL ;
    PORT
      LAYER M4 ;
        RECT  23.676 7.152 23.76 7.176 ;
    END
  END i[67]
  PIN i[68]
    DIRECTION INPUT ;
    USE SIGNAL ;
    PORT
      LAYER M4 ;
        RECT  23.676 7.248 23.76 7.272 ;
    END
  END i[68]
  PIN i[69]
    DIRECTION INPUT ;
    USE SIGNAL ;
    PORT
      LAYER M4 ;
        RECT  23.676 7.344 23.76 7.368 ;
    END
  END i[69]
  PIN i[6]
    DIRECTION INPUT ;
    USE SIGNAL ;
    PORT
      LAYER M4 ;
        RECT  23.676 1.296 23.76 1.32 ;
    END
  END i[6]
  PIN i[70]
    DIRECTION INPUT ;
    USE SIGNAL ;
    PORT
      LAYER M4 ;
        RECT  23.676 7.44 23.76 7.464 ;
    END
  END i[70]
  PIN i[71]
    DIRECTION INPUT ;
    USE SIGNAL ;
    PORT
      LAYER M4 ;
        RECT  23.676 7.536 23.76 7.56 ;
    END
  END i[71]
  PIN i[72]
    DIRECTION INPUT ;
    USE SIGNAL ;
    PORT
      LAYER M4 ;
        RECT  23.676 7.632 23.76 7.656 ;
    END
  END i[72]
  PIN i[73]
    DIRECTION INPUT ;
    USE SIGNAL ;
    PORT
      LAYER M4 ;
        RECT  23.676 7.728 23.76 7.752 ;
    END
  END i[73]
  PIN i[74]
    DIRECTION INPUT ;
    USE SIGNAL ;
    PORT
      LAYER M4 ;
        RECT  23.676 7.824 23.76 7.848 ;
    END
  END i[74]
  PIN i[75]
    DIRECTION INPUT ;
    USE SIGNAL ;
    PORT
      LAYER M4 ;
        RECT  23.676 7.92 23.76 7.944 ;
    END
  END i[75]
  PIN i[76]
    DIRECTION INPUT ;
    USE SIGNAL ;
    PORT
      LAYER M4 ;
        RECT  23.676 8.016 23.76 8.04 ;
    END
  END i[76]
  PIN i[77]
    DIRECTION INPUT ;
    USE SIGNAL ;
    PORT
      LAYER M4 ;
        RECT  23.676 8.112 23.76 8.136 ;
    END
  END i[77]
  PIN i[78]
    DIRECTION INPUT ;
    USE SIGNAL ;
    PORT
      LAYER M4 ;
        RECT  23.676 8.208 23.76 8.232 ;
    END
  END i[78]
  PIN i[79]
    DIRECTION INPUT ;
    USE SIGNAL ;
    PORT
      LAYER M4 ;
        RECT  23.676 8.304 23.76 8.328 ;
    END
  END i[79]
  PIN i[7]
    DIRECTION INPUT ;
    USE SIGNAL ;
    PORT
      LAYER M4 ;
        RECT  23.676 1.392 23.76 1.416 ;
    END
  END i[7]
  PIN i[80]
    DIRECTION INPUT ;
    USE SIGNAL ;
    PORT
      LAYER M4 ;
        RECT  23.676 8.4 23.76 8.424 ;
    END
  END i[80]
  PIN i[81]
    DIRECTION INPUT ;
    USE SIGNAL ;
    PORT
      LAYER M4 ;
        RECT  23.676 8.496 23.76 8.52 ;
    END
  END i[81]
  PIN i[82]
    DIRECTION INPUT ;
    USE SIGNAL ;
    PORT
      LAYER M4 ;
        RECT  23.676 8.592 23.76 8.616 ;
    END
  END i[82]
  PIN i[83]
    DIRECTION INPUT ;
    USE SIGNAL ;
    PORT
      LAYER M4 ;
        RECT  23.676 8.688 23.76 8.712 ;
    END
  END i[83]
  PIN i[84]
    DIRECTION INPUT ;
    USE SIGNAL ;
    PORT
      LAYER M4 ;
        RECT  23.676 8.784 23.76 8.808 ;
    END
  END i[84]
  PIN i[85]
    DIRECTION INPUT ;
    USE SIGNAL ;
    PORT
      LAYER M4 ;
        RECT  23.676 8.88 23.76 8.904 ;
    END
  END i[85]
  PIN i[86]
    DIRECTION INPUT ;
    USE SIGNAL ;
    PORT
      LAYER M4 ;
        RECT  23.676 8.976 23.76 9 ;
    END
  END i[86]
  PIN i[87]
    DIRECTION INPUT ;
    USE SIGNAL ;
    PORT
      LAYER M4 ;
        RECT  23.676 9.072 23.76 9.096 ;
    END
  END i[87]
  PIN i[88]
    DIRECTION INPUT ;
    USE SIGNAL ;
    PORT
      LAYER M4 ;
        RECT  23.676 9.168 23.76 9.192 ;
    END
  END i[88]
  PIN i[89]
    DIRECTION INPUT ;
    USE SIGNAL ;
    PORT
      LAYER M4 ;
        RECT  23.676 9.264 23.76 9.288 ;
    END
  END i[89]
  PIN i[8]
    DIRECTION INPUT ;
    USE SIGNAL ;
    PORT
      LAYER M4 ;
        RECT  23.676 1.488 23.76 1.512 ;
    END
  END i[8]
  PIN i[90]
    DIRECTION INPUT ;
    USE SIGNAL ;
    PORT
      LAYER M4 ;
        RECT  23.676 9.36 23.76 9.384 ;
    END
  END i[90]
  PIN i[91]
    DIRECTION INPUT ;
    USE SIGNAL ;
    PORT
      LAYER M4 ;
        RECT  23.676 9.456 23.76 9.48 ;
    END
  END i[91]
  PIN i[92]
    DIRECTION INPUT ;
    USE SIGNAL ;
    PORT
      LAYER M4 ;
        RECT  23.676 9.552 23.76 9.576 ;
    END
  END i[92]
  PIN i[93]
    DIRECTION INPUT ;
    USE SIGNAL ;
    PORT
      LAYER M4 ;
        RECT  23.676 9.648 23.76 9.672 ;
    END
  END i[93]
  PIN i[94]
    DIRECTION INPUT ;
    USE SIGNAL ;
    PORT
      LAYER M4 ;
        RECT  23.676 9.744 23.76 9.768 ;
    END
  END i[94]
  PIN i[95]
    DIRECTION INPUT ;
    USE SIGNAL ;
    PORT
      LAYER M4 ;
        RECT  23.676 9.84 23.76 9.864 ;
    END
  END i[95]
  PIN i[96]
    DIRECTION INPUT ;
    USE SIGNAL ;
    PORT
      LAYER M4 ;
        RECT  23.676 3.792 23.76 3.816 ;
    END
  END i[96]
  PIN i[97]
    DIRECTION INPUT ;
    USE SIGNAL ;
    PORT
      LAYER M4 ;
        RECT  23.676 3.888 23.76 3.912 ;
    END
  END i[97]
  PIN i[98]
    DIRECTION INPUT ;
    USE SIGNAL ;
    PORT
      LAYER M4 ;
        RECT  23.676 3.984 23.76 4.008 ;
    END
  END i[98]
  PIN i[99]
    DIRECTION INPUT ;
    USE SIGNAL ;
    PORT
      LAYER M4 ;
        RECT  23.676 4.08 23.76 4.104 ;
    END
  END i[99]
  PIN i[9]
    DIRECTION INPUT ;
    USE SIGNAL ;
    PORT
      LAYER M4 ;
        RECT  23.676 1.584 23.76 1.608 ;
    END
  END i[9]
  PIN o[0]
    DIRECTION OUTPUT ;
    USE SIGNAL ;
    PORT
      LAYER M4 ;
        RECT  0 26.448 0.084 26.472 ;
    END
  END o[0]
  PIN o[100]
    DIRECTION OUTPUT ;
    USE SIGNAL ;
    PORT
      LAYER M4 ;
        RECT  0 14.544 0.084 14.568 ;
    END
  END o[100]
  PIN o[101]
    DIRECTION OUTPUT ;
    USE SIGNAL ;
    PORT
      LAYER M4 ;
        RECT  0 14.64 0.084 14.664 ;
    END
  END o[101]
  PIN o[102]
    DIRECTION OUTPUT ;
    USE SIGNAL ;
    PORT
      LAYER M4 ;
        RECT  0 14.736 0.084 14.76 ;
    END
  END o[102]
  PIN o[103]
    DIRECTION OUTPUT ;
    USE SIGNAL ;
    PORT
      LAYER M4 ;
        RECT  0 14.832 0.084 14.856 ;
    END
  END o[103]
  PIN o[104]
    DIRECTION OUTPUT ;
    USE SIGNAL ;
    PORT
      LAYER M4 ;
        RECT  0 14.928 0.084 14.952 ;
    END
  END o[104]
  PIN o[105]
    DIRECTION OUTPUT ;
    USE SIGNAL ;
    PORT
      LAYER M4 ;
        RECT  0 15.024 0.084 15.048 ;
    END
  END o[105]
  PIN o[106]
    DIRECTION OUTPUT ;
    USE SIGNAL ;
    PORT
      LAYER M4 ;
        RECT  0 15.12 0.084 15.144 ;
    END
  END o[106]
  PIN o[107]
    DIRECTION OUTPUT ;
    USE SIGNAL ;
    PORT
      LAYER M4 ;
        RECT  0 15.216 0.084 15.24 ;
    END
  END o[107]
  PIN o[108]
    DIRECTION OUTPUT ;
    USE SIGNAL ;
    PORT
      LAYER M4 ;
        RECT  0 15.312 0.084 15.336 ;
    END
  END o[108]
  PIN o[109]
    DIRECTION OUTPUT ;
    USE SIGNAL ;
    PORT
      LAYER M4 ;
        RECT  0 15.408 0.084 15.432 ;
    END
  END o[109]
  PIN o[10]
    DIRECTION OUTPUT ;
    USE SIGNAL ;
    PORT
      LAYER M4 ;
        RECT  0 27.408 0.084 27.432 ;
    END
  END o[10]
  PIN o[110]
    DIRECTION OUTPUT ;
    USE SIGNAL ;
    PORT
      LAYER M4 ;
        RECT  0 15.504 0.084 15.528 ;
    END
  END o[110]
  PIN o[111]
    DIRECTION OUTPUT ;
    USE SIGNAL ;
    PORT
      LAYER M4 ;
        RECT  0 15.6 0.084 15.624 ;
    END
  END o[111]
  PIN o[112]
    DIRECTION OUTPUT ;
    USE SIGNAL ;
    PORT
      LAYER M4 ;
        RECT  0 15.696 0.084 15.72 ;
    END
  END o[112]
  PIN o[113]
    DIRECTION OUTPUT ;
    USE SIGNAL ;
    PORT
      LAYER M4 ;
        RECT  0 15.792 0.084 15.816 ;
    END
  END o[113]
  PIN o[114]
    DIRECTION OUTPUT ;
    USE SIGNAL ;
    PORT
      LAYER M4 ;
        RECT  0 15.888 0.084 15.912 ;
    END
  END o[114]
  PIN o[115]
    DIRECTION OUTPUT ;
    USE SIGNAL ;
    PORT
      LAYER M4 ;
        RECT  0 15.984 0.084 16.008 ;
    END
  END o[115]
  PIN o[116]
    DIRECTION OUTPUT ;
    USE SIGNAL ;
    PORT
      LAYER M4 ;
        RECT  0 16.08 0.084 16.104 ;
    END
  END o[116]
  PIN o[117]
    DIRECTION OUTPUT ;
    USE SIGNAL ;
    PORT
      LAYER M4 ;
        RECT  0 16.176 0.084 16.2 ;
    END
  END o[117]
  PIN o[118]
    DIRECTION OUTPUT ;
    USE SIGNAL ;
    PORT
      LAYER M4 ;
        RECT  0 16.272 0.084 16.296 ;
    END
  END o[118]
  PIN o[119]
    DIRECTION OUTPUT ;
    USE SIGNAL ;
    PORT
      LAYER M4 ;
        RECT  0 16.368 0.084 16.392 ;
    END
  END o[119]
  PIN o[11]
    DIRECTION OUTPUT ;
    USE SIGNAL ;
    PORT
      LAYER M4 ;
        RECT  0 27.504 0.084 27.528 ;
    END
  END o[11]
  PIN o[120]
    DIRECTION OUTPUT ;
    USE SIGNAL ;
    PORT
      LAYER M4 ;
        RECT  0 16.464 0.084 16.488 ;
    END
  END o[120]
  PIN o[121]
    DIRECTION OUTPUT ;
    USE SIGNAL ;
    PORT
      LAYER M4 ;
        RECT  0 16.56 0.084 16.584 ;
    END
  END o[121]
  PIN o[122]
    DIRECTION OUTPUT ;
    USE SIGNAL ;
    PORT
      LAYER M4 ;
        RECT  0 16.656 0.084 16.68 ;
    END
  END o[122]
  PIN o[123]
    DIRECTION OUTPUT ;
    USE SIGNAL ;
    PORT
      LAYER M4 ;
        RECT  0 16.752 0.084 16.776 ;
    END
  END o[123]
  PIN o[124]
    DIRECTION OUTPUT ;
    USE SIGNAL ;
    PORT
      LAYER M4 ;
        RECT  0 16.848 0.084 16.872 ;
    END
  END o[124]
  PIN o[125]
    DIRECTION OUTPUT ;
    USE SIGNAL ;
    PORT
      LAYER M4 ;
        RECT  0 16.944 0.084 16.968 ;
    END
  END o[125]
  PIN o[126]
    DIRECTION OUTPUT ;
    USE SIGNAL ;
    PORT
      LAYER M4 ;
        RECT  0 17.04 0.084 17.064 ;
    END
  END o[126]
  PIN o[127]
    DIRECTION OUTPUT ;
    USE SIGNAL ;
    PORT
      LAYER M4 ;
        RECT  0 17.136 0.084 17.16 ;
    END
  END o[127]
  PIN o[128]
    DIRECTION OUTPUT ;
    USE SIGNAL ;
    PORT
      LAYER M4 ;
        RECT  0 11.088 0.084 11.112 ;
    END
  END o[128]
  PIN o[129]
    DIRECTION OUTPUT ;
    USE SIGNAL ;
    PORT
      LAYER M4 ;
        RECT  0 11.184 0.084 11.208 ;
    END
  END o[129]
  PIN o[12]
    DIRECTION OUTPUT ;
    USE SIGNAL ;
    PORT
      LAYER M4 ;
        RECT  0 27.6 0.084 27.624 ;
    END
  END o[12]
  PIN o[130]
    DIRECTION OUTPUT ;
    USE SIGNAL ;
    PORT
      LAYER M4 ;
        RECT  0 11.28 0.084 11.304 ;
    END
  END o[130]
  PIN o[131]
    DIRECTION OUTPUT ;
    USE SIGNAL ;
    PORT
      LAYER M4 ;
        RECT  0 11.376 0.084 11.4 ;
    END
  END o[131]
  PIN o[132]
    DIRECTION OUTPUT ;
    USE SIGNAL ;
    PORT
      LAYER M4 ;
        RECT  0 11.472 0.084 11.496 ;
    END
  END o[132]
  PIN o[133]
    DIRECTION OUTPUT ;
    USE SIGNAL ;
    PORT
      LAYER M4 ;
        RECT  0 11.568 0.084 11.592 ;
    END
  END o[133]
  PIN o[134]
    DIRECTION OUTPUT ;
    USE SIGNAL ;
    PORT
      LAYER M4 ;
        RECT  0 11.664 0.084 11.688 ;
    END
  END o[134]
  PIN o[135]
    DIRECTION OUTPUT ;
    USE SIGNAL ;
    PORT
      LAYER M4 ;
        RECT  0 11.76 0.084 11.784 ;
    END
  END o[135]
  PIN o[136]
    DIRECTION OUTPUT ;
    USE SIGNAL ;
    PORT
      LAYER M4 ;
        RECT  0 11.856 0.084 11.88 ;
    END
  END o[136]
  PIN o[137]
    DIRECTION OUTPUT ;
    USE SIGNAL ;
    PORT
      LAYER M4 ;
        RECT  0 11.952 0.084 11.976 ;
    END
  END o[137]
  PIN o[138]
    DIRECTION OUTPUT ;
    USE SIGNAL ;
    PORT
      LAYER M4 ;
        RECT  0 12.048 0.084 12.072 ;
    END
  END o[138]
  PIN o[139]
    DIRECTION OUTPUT ;
    USE SIGNAL ;
    PORT
      LAYER M4 ;
        RECT  0 12.144 0.084 12.168 ;
    END
  END o[139]
  PIN o[13]
    DIRECTION OUTPUT ;
    USE SIGNAL ;
    PORT
      LAYER M4 ;
        RECT  0 27.696 0.084 27.72 ;
    END
  END o[13]
  PIN o[140]
    DIRECTION OUTPUT ;
    USE SIGNAL ;
    PORT
      LAYER M4 ;
        RECT  0 12.24 0.084 12.264 ;
    END
  END o[140]
  PIN o[141]
    DIRECTION OUTPUT ;
    USE SIGNAL ;
    PORT
      LAYER M4 ;
        RECT  0 12.336 0.084 12.36 ;
    END
  END o[141]
  PIN o[142]
    DIRECTION OUTPUT ;
    USE SIGNAL ;
    PORT
      LAYER M4 ;
        RECT  0 12.432 0.084 12.456 ;
    END
  END o[142]
  PIN o[143]
    DIRECTION OUTPUT ;
    USE SIGNAL ;
    PORT
      LAYER M4 ;
        RECT  0 12.528 0.084 12.552 ;
    END
  END o[143]
  PIN o[144]
    DIRECTION OUTPUT ;
    USE SIGNAL ;
    PORT
      LAYER M4 ;
        RECT  0 12.624 0.084 12.648 ;
    END
  END o[144]
  PIN o[145]
    DIRECTION OUTPUT ;
    USE SIGNAL ;
    PORT
      LAYER M4 ;
        RECT  0 12.72 0.084 12.744 ;
    END
  END o[145]
  PIN o[146]
    DIRECTION OUTPUT ;
    USE SIGNAL ;
    PORT
      LAYER M4 ;
        RECT  0 12.816 0.084 12.84 ;
    END
  END o[146]
  PIN o[147]
    DIRECTION OUTPUT ;
    USE SIGNAL ;
    PORT
      LAYER M4 ;
        RECT  0 12.912 0.084 12.936 ;
    END
  END o[147]
  PIN o[148]
    DIRECTION OUTPUT ;
    USE SIGNAL ;
    PORT
      LAYER M4 ;
        RECT  0 13.008 0.084 13.032 ;
    END
  END o[148]
  PIN o[149]
    DIRECTION OUTPUT ;
    USE SIGNAL ;
    PORT
      LAYER M4 ;
        RECT  0 13.104 0.084 13.128 ;
    END
  END o[149]
  PIN o[14]
    DIRECTION OUTPUT ;
    USE SIGNAL ;
    PORT
      LAYER M4 ;
        RECT  0 27.792 0.084 27.816 ;
    END
  END o[14]
  PIN o[150]
    DIRECTION OUTPUT ;
    USE SIGNAL ;
    PORT
      LAYER M4 ;
        RECT  0 13.2 0.084 13.224 ;
    END
  END o[150]
  PIN o[151]
    DIRECTION OUTPUT ;
    USE SIGNAL ;
    PORT
      LAYER M4 ;
        RECT  0 13.296 0.084 13.32 ;
    END
  END o[151]
  PIN o[152]
    DIRECTION OUTPUT ;
    USE SIGNAL ;
    PORT
      LAYER M4 ;
        RECT  0 13.392 0.084 13.416 ;
    END
  END o[152]
  PIN o[153]
    DIRECTION OUTPUT ;
    USE SIGNAL ;
    PORT
      LAYER M4 ;
        RECT  0 13.488 0.084 13.512 ;
    END
  END o[153]
  PIN o[154]
    DIRECTION OUTPUT ;
    USE SIGNAL ;
    PORT
      LAYER M4 ;
        RECT  0 13.584 0.084 13.608 ;
    END
  END o[154]
  PIN o[155]
    DIRECTION OUTPUT ;
    USE SIGNAL ;
    PORT
      LAYER M4 ;
        RECT  0 13.68 0.084 13.704 ;
    END
  END o[155]
  PIN o[156]
    DIRECTION OUTPUT ;
    USE SIGNAL ;
    PORT
      LAYER M4 ;
        RECT  0 13.776 0.084 13.8 ;
    END
  END o[156]
  PIN o[157]
    DIRECTION OUTPUT ;
    USE SIGNAL ;
    PORT
      LAYER M4 ;
        RECT  0 13.872 0.084 13.896 ;
    END
  END o[157]
  PIN o[158]
    DIRECTION OUTPUT ;
    USE SIGNAL ;
    PORT
      LAYER M4 ;
        RECT  0 13.968 0.084 13.992 ;
    END
  END o[158]
  PIN o[159]
    DIRECTION OUTPUT ;
    USE SIGNAL ;
    PORT
      LAYER M4 ;
        RECT  0 14.064 0.084 14.088 ;
    END
  END o[159]
  PIN o[15]
    DIRECTION OUTPUT ;
    USE SIGNAL ;
    PORT
      LAYER M4 ;
        RECT  0 27.888 0.084 27.912 ;
    END
  END o[15]
  PIN o[160]
    DIRECTION OUTPUT ;
    USE SIGNAL ;
    PORT
      LAYER M4 ;
        RECT  0 23.376 0.084 23.4 ;
    END
  END o[160]
  PIN o[161]
    DIRECTION OUTPUT ;
    USE SIGNAL ;
    PORT
      LAYER M4 ;
        RECT  0 23.472 0.084 23.496 ;
    END
  END o[161]
  PIN o[162]
    DIRECTION OUTPUT ;
    USE SIGNAL ;
    PORT
      LAYER M4 ;
        RECT  0 23.568 0.084 23.592 ;
    END
  END o[162]
  PIN o[163]
    DIRECTION OUTPUT ;
    USE SIGNAL ;
    PORT
      LAYER M4 ;
        RECT  0 23.664 0.084 23.688 ;
    END
  END o[163]
  PIN o[164]
    DIRECTION OUTPUT ;
    USE SIGNAL ;
    PORT
      LAYER M4 ;
        RECT  0 23.76 0.084 23.784 ;
    END
  END o[164]
  PIN o[165]
    DIRECTION OUTPUT ;
    USE SIGNAL ;
    PORT
      LAYER M4 ;
        RECT  0 23.856 0.084 23.88 ;
    END
  END o[165]
  PIN o[166]
    DIRECTION OUTPUT ;
    USE SIGNAL ;
    PORT
      LAYER M4 ;
        RECT  0 23.952 0.084 23.976 ;
    END
  END o[166]
  PIN o[167]
    DIRECTION OUTPUT ;
    USE SIGNAL ;
    PORT
      LAYER M4 ;
        RECT  0 24.048 0.084 24.072 ;
    END
  END o[167]
  PIN o[168]
    DIRECTION OUTPUT ;
    USE SIGNAL ;
    PORT
      LAYER M4 ;
        RECT  0 24.144 0.084 24.168 ;
    END
  END o[168]
  PIN o[169]
    DIRECTION OUTPUT ;
    USE SIGNAL ;
    PORT
      LAYER M4 ;
        RECT  0 24.24 0.084 24.264 ;
    END
  END o[169]
  PIN o[16]
    DIRECTION OUTPUT ;
    USE SIGNAL ;
    PORT
      LAYER M4 ;
        RECT  0 27.984 0.084 28.008 ;
    END
  END o[16]
  PIN o[170]
    DIRECTION OUTPUT ;
    USE SIGNAL ;
    PORT
      LAYER M4 ;
        RECT  0 24.336 0.084 24.36 ;
    END
  END o[170]
  PIN o[171]
    DIRECTION OUTPUT ;
    USE SIGNAL ;
    PORT
      LAYER M4 ;
        RECT  0 24.432 0.084 24.456 ;
    END
  END o[171]
  PIN o[172]
    DIRECTION OUTPUT ;
    USE SIGNAL ;
    PORT
      LAYER M4 ;
        RECT  0 24.528 0.084 24.552 ;
    END
  END o[172]
  PIN o[173]
    DIRECTION OUTPUT ;
    USE SIGNAL ;
    PORT
      LAYER M4 ;
        RECT  0 24.624 0.084 24.648 ;
    END
  END o[173]
  PIN o[174]
    DIRECTION OUTPUT ;
    USE SIGNAL ;
    PORT
      LAYER M4 ;
        RECT  0 24.72 0.084 24.744 ;
    END
  END o[174]
  PIN o[175]
    DIRECTION OUTPUT ;
    USE SIGNAL ;
    PORT
      LAYER M4 ;
        RECT  0 24.816 0.084 24.84 ;
    END
  END o[175]
  PIN o[176]
    DIRECTION OUTPUT ;
    USE SIGNAL ;
    PORT
      LAYER M4 ;
        RECT  0 24.912 0.084 24.936 ;
    END
  END o[176]
  PIN o[177]
    DIRECTION OUTPUT ;
    USE SIGNAL ;
    PORT
      LAYER M4 ;
        RECT  0 25.008 0.084 25.032 ;
    END
  END o[177]
  PIN o[178]
    DIRECTION OUTPUT ;
    USE SIGNAL ;
    PORT
      LAYER M4 ;
        RECT  0 25.104 0.084 25.128 ;
    END
  END o[178]
  PIN o[179]
    DIRECTION OUTPUT ;
    USE SIGNAL ;
    PORT
      LAYER M4 ;
        RECT  0 25.2 0.084 25.224 ;
    END
  END o[179]
  PIN o[17]
    DIRECTION OUTPUT ;
    USE SIGNAL ;
    PORT
      LAYER M4 ;
        RECT  0 28.08 0.084 28.104 ;
    END
  END o[17]
  PIN o[180]
    DIRECTION OUTPUT ;
    USE SIGNAL ;
    PORT
      LAYER M4 ;
        RECT  0 25.296 0.084 25.32 ;
    END
  END o[180]
  PIN o[181]
    DIRECTION OUTPUT ;
    USE SIGNAL ;
    PORT
      LAYER M4 ;
        RECT  0 25.392 0.084 25.416 ;
    END
  END o[181]
  PIN o[182]
    DIRECTION OUTPUT ;
    USE SIGNAL ;
    PORT
      LAYER M4 ;
        RECT  0 25.488 0.084 25.512 ;
    END
  END o[182]
  PIN o[183]
    DIRECTION OUTPUT ;
    USE SIGNAL ;
    PORT
      LAYER M4 ;
        RECT  0 25.584 0.084 25.608 ;
    END
  END o[183]
  PIN o[184]
    DIRECTION OUTPUT ;
    USE SIGNAL ;
    PORT
      LAYER M4 ;
        RECT  0 25.68 0.084 25.704 ;
    END
  END o[184]
  PIN o[185]
    DIRECTION OUTPUT ;
    USE SIGNAL ;
    PORT
      LAYER M4 ;
        RECT  0 25.776 0.084 25.8 ;
    END
  END o[185]
  PIN o[186]
    DIRECTION OUTPUT ;
    USE SIGNAL ;
    PORT
      LAYER M4 ;
        RECT  0 25.872 0.084 25.896 ;
    END
  END o[186]
  PIN o[187]
    DIRECTION OUTPUT ;
    USE SIGNAL ;
    PORT
      LAYER M4 ;
        RECT  0 25.968 0.084 25.992 ;
    END
  END o[187]
  PIN o[188]
    DIRECTION OUTPUT ;
    USE SIGNAL ;
    PORT
      LAYER M4 ;
        RECT  0 26.064 0.084 26.088 ;
    END
  END o[188]
  PIN o[189]
    DIRECTION OUTPUT ;
    USE SIGNAL ;
    PORT
      LAYER M4 ;
        RECT  0 26.16 0.084 26.184 ;
    END
  END o[189]
  PIN o[18]
    DIRECTION OUTPUT ;
    USE SIGNAL ;
    PORT
      LAYER M4 ;
        RECT  0 28.176 0.084 28.2 ;
    END
  END o[18]
  PIN o[190]
    DIRECTION OUTPUT ;
    USE SIGNAL ;
    PORT
      LAYER M4 ;
        RECT  0 26.256 0.084 26.28 ;
    END
  END o[190]
  PIN o[191]
    DIRECTION OUTPUT ;
    USE SIGNAL ;
    PORT
      LAYER M4 ;
        RECT  0 26.352 0.084 26.376 ;
    END
  END o[191]
  PIN o[192]
    DIRECTION OUTPUT ;
    USE SIGNAL ;
    PORT
      LAYER M4 ;
        RECT  0 7.248 0.084 7.272 ;
    END
  END o[192]
  PIN o[193]
    DIRECTION OUTPUT ;
    USE SIGNAL ;
    PORT
      LAYER M4 ;
        RECT  0 7.344 0.084 7.368 ;
    END
  END o[193]
  PIN o[194]
    DIRECTION OUTPUT ;
    USE SIGNAL ;
    PORT
      LAYER M4 ;
        RECT  0 7.44 0.084 7.464 ;
    END
  END o[194]
  PIN o[195]
    DIRECTION OUTPUT ;
    USE SIGNAL ;
    PORT
      LAYER M4 ;
        RECT  0 7.536 0.084 7.56 ;
    END
  END o[195]
  PIN o[196]
    DIRECTION OUTPUT ;
    USE SIGNAL ;
    PORT
      LAYER M4 ;
        RECT  0 7.632 0.084 7.656 ;
    END
  END o[196]
  PIN o[197]
    DIRECTION OUTPUT ;
    USE SIGNAL ;
    PORT
      LAYER M4 ;
        RECT  0 7.728 0.084 7.752 ;
    END
  END o[197]
  PIN o[198]
    DIRECTION OUTPUT ;
    USE SIGNAL ;
    PORT
      LAYER M4 ;
        RECT  0 7.824 0.084 7.848 ;
    END
  END o[198]
  PIN o[199]
    DIRECTION OUTPUT ;
    USE SIGNAL ;
    PORT
      LAYER M4 ;
        RECT  0 7.92 0.084 7.944 ;
    END
  END o[199]
  PIN o[19]
    DIRECTION OUTPUT ;
    USE SIGNAL ;
    PORT
      LAYER M4 ;
        RECT  0 28.272 0.084 28.296 ;
    END
  END o[19]
  PIN o[1]
    DIRECTION OUTPUT ;
    USE SIGNAL ;
    PORT
      LAYER M4 ;
        RECT  0 26.544 0.084 26.568 ;
    END
  END o[1]
  PIN o[200]
    DIRECTION OUTPUT ;
    USE SIGNAL ;
    PORT
      LAYER M4 ;
        RECT  0 8.016 0.084 8.04 ;
    END
  END o[200]
  PIN o[201]
    DIRECTION OUTPUT ;
    USE SIGNAL ;
    PORT
      LAYER M4 ;
        RECT  0 8.112 0.084 8.136 ;
    END
  END o[201]
  PIN o[202]
    DIRECTION OUTPUT ;
    USE SIGNAL ;
    PORT
      LAYER M4 ;
        RECT  0 8.208 0.084 8.232 ;
    END
  END o[202]
  PIN o[203]
    DIRECTION OUTPUT ;
    USE SIGNAL ;
    PORT
      LAYER M4 ;
        RECT  0 8.304 0.084 8.328 ;
    END
  END o[203]
  PIN o[204]
    DIRECTION OUTPUT ;
    USE SIGNAL ;
    PORT
      LAYER M4 ;
        RECT  0 8.4 0.084 8.424 ;
    END
  END o[204]
  PIN o[205]
    DIRECTION OUTPUT ;
    USE SIGNAL ;
    PORT
      LAYER M4 ;
        RECT  0 8.496 0.084 8.52 ;
    END
  END o[205]
  PIN o[206]
    DIRECTION OUTPUT ;
    USE SIGNAL ;
    PORT
      LAYER M4 ;
        RECT  0 8.592 0.084 8.616 ;
    END
  END o[206]
  PIN o[207]
    DIRECTION OUTPUT ;
    USE SIGNAL ;
    PORT
      LAYER M4 ;
        RECT  0 8.688 0.084 8.712 ;
    END
  END o[207]
  PIN o[208]
    DIRECTION OUTPUT ;
    USE SIGNAL ;
    PORT
      LAYER M4 ;
        RECT  0 8.784 0.084 8.808 ;
    END
  END o[208]
  PIN o[209]
    DIRECTION OUTPUT ;
    USE SIGNAL ;
    PORT
      LAYER M4 ;
        RECT  0 8.88 0.084 8.904 ;
    END
  END o[209]
  PIN o[20]
    DIRECTION OUTPUT ;
    USE SIGNAL ;
    PORT
      LAYER M4 ;
        RECT  0 28.368 0.084 28.392 ;
    END
  END o[20]
  PIN o[210]
    DIRECTION OUTPUT ;
    USE SIGNAL ;
    PORT
      LAYER M4 ;
        RECT  0 8.976 0.084 9 ;
    END
  END o[210]
  PIN o[211]
    DIRECTION OUTPUT ;
    USE SIGNAL ;
    PORT
      LAYER M4 ;
        RECT  0 9.072 0.084 9.096 ;
    END
  END o[211]
  PIN o[212]
    DIRECTION OUTPUT ;
    USE SIGNAL ;
    PORT
      LAYER M4 ;
        RECT  0 9.168 0.084 9.192 ;
    END
  END o[212]
  PIN o[213]
    DIRECTION OUTPUT ;
    USE SIGNAL ;
    PORT
      LAYER M4 ;
        RECT  0 9.264 0.084 9.288 ;
    END
  END o[213]
  PIN o[214]
    DIRECTION OUTPUT ;
    USE SIGNAL ;
    PORT
      LAYER M4 ;
        RECT  0 9.36 0.084 9.384 ;
    END
  END o[214]
  PIN o[215]
    DIRECTION OUTPUT ;
    USE SIGNAL ;
    PORT
      LAYER M4 ;
        RECT  0 9.456 0.084 9.48 ;
    END
  END o[215]
  PIN o[216]
    DIRECTION OUTPUT ;
    USE SIGNAL ;
    PORT
      LAYER M4 ;
        RECT  0 9.552 0.084 9.576 ;
    END
  END o[216]
  PIN o[217]
    DIRECTION OUTPUT ;
    USE SIGNAL ;
    PORT
      LAYER M4 ;
        RECT  0 9.648 0.084 9.672 ;
    END
  END o[217]
  PIN o[218]
    DIRECTION OUTPUT ;
    USE SIGNAL ;
    PORT
      LAYER M4 ;
        RECT  0 9.744 0.084 9.768 ;
    END
  END o[218]
  PIN o[219]
    DIRECTION OUTPUT ;
    USE SIGNAL ;
    PORT
      LAYER M4 ;
        RECT  0 9.84 0.084 9.864 ;
    END
  END o[219]
  PIN o[21]
    DIRECTION OUTPUT ;
    USE SIGNAL ;
    PORT
      LAYER M4 ;
        RECT  0 28.464 0.084 28.488 ;
    END
  END o[21]
  PIN o[220]
    DIRECTION OUTPUT ;
    USE SIGNAL ;
    PORT
      LAYER M4 ;
        RECT  0 9.936 0.084 9.96 ;
    END
  END o[220]
  PIN o[221]
    DIRECTION OUTPUT ;
    USE SIGNAL ;
    PORT
      LAYER M4 ;
        RECT  0 10.032 0.084 10.056 ;
    END
  END o[221]
  PIN o[222]
    DIRECTION OUTPUT ;
    USE SIGNAL ;
    PORT
      LAYER M4 ;
        RECT  0 10.128 0.084 10.152 ;
    END
  END o[222]
  PIN o[223]
    DIRECTION OUTPUT ;
    USE SIGNAL ;
    PORT
      LAYER M4 ;
        RECT  0 10.224 0.084 10.248 ;
    END
  END o[223]
  PIN o[224]
    DIRECTION OUTPUT ;
    USE SIGNAL ;
    PORT
      LAYER M4 ;
        RECT  0 4.176 0.084 4.2 ;
    END
  END o[224]
  PIN o[225]
    DIRECTION OUTPUT ;
    USE SIGNAL ;
    PORT
      LAYER M4 ;
        RECT  0 4.272 0.084 4.296 ;
    END
  END o[225]
  PIN o[226]
    DIRECTION OUTPUT ;
    USE SIGNAL ;
    PORT
      LAYER M4 ;
        RECT  0 4.368 0.084 4.392 ;
    END
  END o[226]
  PIN o[227]
    DIRECTION OUTPUT ;
    USE SIGNAL ;
    PORT
      LAYER M4 ;
        RECT  0 4.464 0.084 4.488 ;
    END
  END o[227]
  PIN o[228]
    DIRECTION OUTPUT ;
    USE SIGNAL ;
    PORT
      LAYER M4 ;
        RECT  0 4.56 0.084 4.584 ;
    END
  END o[228]
  PIN o[229]
    DIRECTION OUTPUT ;
    USE SIGNAL ;
    PORT
      LAYER M4 ;
        RECT  0 4.656 0.084 4.68 ;
    END
  END o[229]
  PIN o[22]
    DIRECTION OUTPUT ;
    USE SIGNAL ;
    PORT
      LAYER M4 ;
        RECT  0 28.56 0.084 28.584 ;
    END
  END o[22]
  PIN o[230]
    DIRECTION OUTPUT ;
    USE SIGNAL ;
    PORT
      LAYER M4 ;
        RECT  0 4.752 0.084 4.776 ;
    END
  END o[230]
  PIN o[231]
    DIRECTION OUTPUT ;
    USE SIGNAL ;
    PORT
      LAYER M4 ;
        RECT  0 4.848 0.084 4.872 ;
    END
  END o[231]
  PIN o[232]
    DIRECTION OUTPUT ;
    USE SIGNAL ;
    PORT
      LAYER M4 ;
        RECT  0 4.944 0.084 4.968 ;
    END
  END o[232]
  PIN o[233]
    DIRECTION OUTPUT ;
    USE SIGNAL ;
    PORT
      LAYER M4 ;
        RECT  0 5.04 0.084 5.064 ;
    END
  END o[233]
  PIN o[234]
    DIRECTION OUTPUT ;
    USE SIGNAL ;
    PORT
      LAYER M4 ;
        RECT  0 5.136 0.084 5.16 ;
    END
  END o[234]
  PIN o[235]
    DIRECTION OUTPUT ;
    USE SIGNAL ;
    PORT
      LAYER M4 ;
        RECT  0 5.232 0.084 5.256 ;
    END
  END o[235]
  PIN o[236]
    DIRECTION OUTPUT ;
    USE SIGNAL ;
    PORT
      LAYER M4 ;
        RECT  0 5.328 0.084 5.352 ;
    END
  END o[236]
  PIN o[237]
    DIRECTION OUTPUT ;
    USE SIGNAL ;
    PORT
      LAYER M4 ;
        RECT  0 5.424 0.084 5.448 ;
    END
  END o[237]
  PIN o[238]
    DIRECTION OUTPUT ;
    USE SIGNAL ;
    PORT
      LAYER M4 ;
        RECT  0 5.52 0.084 5.544 ;
    END
  END o[238]
  PIN o[239]
    DIRECTION OUTPUT ;
    USE SIGNAL ;
    PORT
      LAYER M4 ;
        RECT  0 5.616 0.084 5.64 ;
    END
  END o[239]
  PIN o[23]
    DIRECTION OUTPUT ;
    USE SIGNAL ;
    PORT
      LAYER M4 ;
        RECT  0 28.656 0.084 28.68 ;
    END
  END o[23]
  PIN o[240]
    DIRECTION OUTPUT ;
    USE SIGNAL ;
    PORT
      LAYER M4 ;
        RECT  0 5.712 0.084 5.736 ;
    END
  END o[240]
  PIN o[241]
    DIRECTION OUTPUT ;
    USE SIGNAL ;
    PORT
      LAYER M4 ;
        RECT  0 5.808 0.084 5.832 ;
    END
  END o[241]
  PIN o[242]
    DIRECTION OUTPUT ;
    USE SIGNAL ;
    PORT
      LAYER M4 ;
        RECT  0 5.904 0.084 5.928 ;
    END
  END o[242]
  PIN o[243]
    DIRECTION OUTPUT ;
    USE SIGNAL ;
    PORT
      LAYER M4 ;
        RECT  0 6 0.084 6.024 ;
    END
  END o[243]
  PIN o[244]
    DIRECTION OUTPUT ;
    USE SIGNAL ;
    PORT
      LAYER M4 ;
        RECT  0 6.096 0.084 6.12 ;
    END
  END o[244]
  PIN o[245]
    DIRECTION OUTPUT ;
    USE SIGNAL ;
    PORT
      LAYER M4 ;
        RECT  0 6.192 0.084 6.216 ;
    END
  END o[245]
  PIN o[246]
    DIRECTION OUTPUT ;
    USE SIGNAL ;
    PORT
      LAYER M4 ;
        RECT  0 6.288 0.084 6.312 ;
    END
  END o[246]
  PIN o[247]
    DIRECTION OUTPUT ;
    USE SIGNAL ;
    PORT
      LAYER M4 ;
        RECT  0 6.384 0.084 6.408 ;
    END
  END o[247]
  PIN o[248]
    DIRECTION OUTPUT ;
    USE SIGNAL ;
    PORT
      LAYER M4 ;
        RECT  0 6.48 0.084 6.504 ;
    END
  END o[248]
  PIN o[249]
    DIRECTION OUTPUT ;
    USE SIGNAL ;
    PORT
      LAYER M4 ;
        RECT  0 6.576 0.084 6.6 ;
    END
  END o[249]
  PIN o[24]
    DIRECTION OUTPUT ;
    USE SIGNAL ;
    PORT
      LAYER M4 ;
        RECT  0 28.752 0.084 28.776 ;
    END
  END o[24]
  PIN o[250]
    DIRECTION OUTPUT ;
    USE SIGNAL ;
    PORT
      LAYER M4 ;
        RECT  0 6.672 0.084 6.696 ;
    END
  END o[250]
  PIN o[251]
    DIRECTION OUTPUT ;
    USE SIGNAL ;
    PORT
      LAYER M4 ;
        RECT  0 6.768 0.084 6.792 ;
    END
  END o[251]
  PIN o[252]
    DIRECTION OUTPUT ;
    USE SIGNAL ;
    PORT
      LAYER M4 ;
        RECT  0 6.864 0.084 6.888 ;
    END
  END o[252]
  PIN o[253]
    DIRECTION OUTPUT ;
    USE SIGNAL ;
    PORT
      LAYER M4 ;
        RECT  0 6.96 0.084 6.984 ;
    END
  END o[253]
  PIN o[254]
    DIRECTION OUTPUT ;
    USE SIGNAL ;
    PORT
      LAYER M4 ;
        RECT  0 7.056 0.084 7.08 ;
    END
  END o[254]
  PIN o[255]
    DIRECTION OUTPUT ;
    USE SIGNAL ;
    PORT
      LAYER M4 ;
        RECT  0 7.152 0.084 7.176 ;
    END
  END o[255]
  PIN o[256]
    DIRECTION OUTPUT ;
    USE SIGNAL ;
    PORT
      LAYER M4 ;
        RECT  0 3.216 0.084 3.24 ;
    END
  END o[256]
  PIN o[257]
    DIRECTION OUTPUT ;
    USE SIGNAL ;
    PORT
      LAYER M4 ;
        RECT  0 3.312 0.084 3.336 ;
    END
  END o[257]
  PIN o[258]
    DIRECTION OUTPUT ;
    USE SIGNAL ;
    PORT
      LAYER M4 ;
        RECT  0 3.408 0.084 3.432 ;
    END
  END o[258]
  PIN o[259]
    DIRECTION OUTPUT ;
    USE SIGNAL ;
    PORT
      LAYER M4 ;
        RECT  0 3.504 0.084 3.528 ;
    END
  END o[259]
  PIN o[25]
    DIRECTION OUTPUT ;
    USE SIGNAL ;
    PORT
      LAYER M4 ;
        RECT  0 28.848 0.084 28.872 ;
    END
  END o[25]
  PIN o[260]
    DIRECTION OUTPUT ;
    USE SIGNAL ;
    PORT
      LAYER M4 ;
        RECT  0 3.6 0.084 3.624 ;
    END
  END o[260]
  PIN o[261]
    DIRECTION OUTPUT ;
    USE SIGNAL ;
    PORT
      LAYER M4 ;
        RECT  0 3.696 0.084 3.72 ;
    END
  END o[261]
  PIN o[262]
    DIRECTION OUTPUT ;
    USE SIGNAL ;
    PORT
      LAYER M4 ;
        RECT  0 3.792 0.084 3.816 ;
    END
  END o[262]
  PIN o[263]
    DIRECTION OUTPUT ;
    USE SIGNAL ;
    PORT
      LAYER M4 ;
        RECT  0 3.888 0.084 3.912 ;
    END
  END o[263]
  PIN o[264]
    DIRECTION OUTPUT ;
    USE SIGNAL ;
    PORT
      LAYER M4 ;
        RECT  0 3.984 0.084 4.008 ;
    END
  END o[264]
  PIN o[265]
    DIRECTION OUTPUT ;
    USE SIGNAL ;
    PORT
      LAYER M4 ;
        RECT  0 4.08 0.084 4.104 ;
    END
  END o[265]
  PIN o[26]
    DIRECTION OUTPUT ;
    USE SIGNAL ;
    PORT
      LAYER M4 ;
        RECT  0 28.944 0.084 28.968 ;
    END
  END o[26]
  PIN o[27]
    DIRECTION OUTPUT ;
    USE SIGNAL ;
    PORT
      LAYER M4 ;
        RECT  0 29.04 0.084 29.064 ;
    END
  END o[27]
  PIN o[28]
    DIRECTION OUTPUT ;
    USE SIGNAL ;
    PORT
      LAYER M4 ;
        RECT  0 29.136 0.084 29.16 ;
    END
  END o[28]
  PIN o[29]
    DIRECTION OUTPUT ;
    USE SIGNAL ;
    PORT
      LAYER M4 ;
        RECT  0 29.232 0.084 29.256 ;
    END
  END o[29]
  PIN o[2]
    DIRECTION OUTPUT ;
    USE SIGNAL ;
    PORT
      LAYER M4 ;
        RECT  0 26.64 0.084 26.664 ;
    END
  END o[2]
  PIN o[30]
    DIRECTION OUTPUT ;
    USE SIGNAL ;
    PORT
      LAYER M4 ;
        RECT  0 29.328 0.084 29.352 ;
    END
  END o[30]
  PIN o[31]
    DIRECTION OUTPUT ;
    USE SIGNAL ;
    PORT
      LAYER M4 ;
        RECT  0 29.424 0.084 29.448 ;
    END
  END o[31]
  PIN o[32]
    DIRECTION OUTPUT ;
    USE SIGNAL ;
    PORT
      LAYER M4 ;
        RECT  0 20.304 0.084 20.328 ;
    END
  END o[32]
  PIN o[33]
    DIRECTION OUTPUT ;
    USE SIGNAL ;
    PORT
      LAYER M4 ;
        RECT  0 20.4 0.084 20.424 ;
    END
  END o[33]
  PIN o[34]
    DIRECTION OUTPUT ;
    USE SIGNAL ;
    PORT
      LAYER M4 ;
        RECT  0 20.496 0.084 20.52 ;
    END
  END o[34]
  PIN o[35]
    DIRECTION OUTPUT ;
    USE SIGNAL ;
    PORT
      LAYER M4 ;
        RECT  0 20.592 0.084 20.616 ;
    END
  END o[35]
  PIN o[36]
    DIRECTION OUTPUT ;
    USE SIGNAL ;
    PORT
      LAYER M4 ;
        RECT  0 20.688 0.084 20.712 ;
    END
  END o[36]
  PIN o[37]
    DIRECTION OUTPUT ;
    USE SIGNAL ;
    PORT
      LAYER M4 ;
        RECT  0 20.784 0.084 20.808 ;
    END
  END o[37]
  PIN o[38]
    DIRECTION OUTPUT ;
    USE SIGNAL ;
    PORT
      LAYER M4 ;
        RECT  0 20.88 0.084 20.904 ;
    END
  END o[38]
  PIN o[39]
    DIRECTION OUTPUT ;
    USE SIGNAL ;
    PORT
      LAYER M4 ;
        RECT  0 20.976 0.084 21 ;
    END
  END o[39]
  PIN o[3]
    DIRECTION OUTPUT ;
    USE SIGNAL ;
    PORT
      LAYER M4 ;
        RECT  0 26.736 0.084 26.76 ;
    END
  END o[3]
  PIN o[40]
    DIRECTION OUTPUT ;
    USE SIGNAL ;
    PORT
      LAYER M4 ;
        RECT  0 21.072 0.084 21.096 ;
    END
  END o[40]
  PIN o[41]
    DIRECTION OUTPUT ;
    USE SIGNAL ;
    PORT
      LAYER M4 ;
        RECT  0 21.168 0.084 21.192 ;
    END
  END o[41]
  PIN o[42]
    DIRECTION OUTPUT ;
    USE SIGNAL ;
    PORT
      LAYER M4 ;
        RECT  0 21.264 0.084 21.288 ;
    END
  END o[42]
  PIN o[43]
    DIRECTION OUTPUT ;
    USE SIGNAL ;
    PORT
      LAYER M4 ;
        RECT  0 21.36 0.084 21.384 ;
    END
  END o[43]
  PIN o[44]
    DIRECTION OUTPUT ;
    USE SIGNAL ;
    PORT
      LAYER M4 ;
        RECT  0 21.456 0.084 21.48 ;
    END
  END o[44]
  PIN o[45]
    DIRECTION OUTPUT ;
    USE SIGNAL ;
    PORT
      LAYER M4 ;
        RECT  0 21.552 0.084 21.576 ;
    END
  END o[45]
  PIN o[46]
    DIRECTION OUTPUT ;
    USE SIGNAL ;
    PORT
      LAYER M4 ;
        RECT  0 21.648 0.084 21.672 ;
    END
  END o[46]
  PIN o[47]
    DIRECTION OUTPUT ;
    USE SIGNAL ;
    PORT
      LAYER M4 ;
        RECT  0 21.744 0.084 21.768 ;
    END
  END o[47]
  PIN o[48]
    DIRECTION OUTPUT ;
    USE SIGNAL ;
    PORT
      LAYER M4 ;
        RECT  0 21.84 0.084 21.864 ;
    END
  END o[48]
  PIN o[49]
    DIRECTION OUTPUT ;
    USE SIGNAL ;
    PORT
      LAYER M4 ;
        RECT  0 21.936 0.084 21.96 ;
    END
  END o[49]
  PIN o[4]
    DIRECTION OUTPUT ;
    USE SIGNAL ;
    PORT
      LAYER M4 ;
        RECT  0 26.832 0.084 26.856 ;
    END
  END o[4]
  PIN o[50]
    DIRECTION OUTPUT ;
    USE SIGNAL ;
    PORT
      LAYER M4 ;
        RECT  0 22.032 0.084 22.056 ;
    END
  END o[50]
  PIN o[51]
    DIRECTION OUTPUT ;
    USE SIGNAL ;
    PORT
      LAYER M4 ;
        RECT  0 22.128 0.084 22.152 ;
    END
  END o[51]
  PIN o[52]
    DIRECTION OUTPUT ;
    USE SIGNAL ;
    PORT
      LAYER M4 ;
        RECT  0 22.224 0.084 22.248 ;
    END
  END o[52]
  PIN o[53]
    DIRECTION OUTPUT ;
    USE SIGNAL ;
    PORT
      LAYER M4 ;
        RECT  0 22.32 0.084 22.344 ;
    END
  END o[53]
  PIN o[54]
    DIRECTION OUTPUT ;
    USE SIGNAL ;
    PORT
      LAYER M4 ;
        RECT  0 22.416 0.084 22.44 ;
    END
  END o[54]
  PIN o[55]
    DIRECTION OUTPUT ;
    USE SIGNAL ;
    PORT
      LAYER M4 ;
        RECT  0 22.512 0.084 22.536 ;
    END
  END o[55]
  PIN o[56]
    DIRECTION OUTPUT ;
    USE SIGNAL ;
    PORT
      LAYER M4 ;
        RECT  0 22.608 0.084 22.632 ;
    END
  END o[56]
  PIN o[57]
    DIRECTION OUTPUT ;
    USE SIGNAL ;
    PORT
      LAYER M4 ;
        RECT  0 22.704 0.084 22.728 ;
    END
  END o[57]
  PIN o[58]
    DIRECTION OUTPUT ;
    USE SIGNAL ;
    PORT
      LAYER M4 ;
        RECT  0 22.8 0.084 22.824 ;
    END
  END o[58]
  PIN o[59]
    DIRECTION OUTPUT ;
    USE SIGNAL ;
    PORT
      LAYER M4 ;
        RECT  0 22.896 0.084 22.92 ;
    END
  END o[59]
  PIN o[5]
    DIRECTION OUTPUT ;
    USE SIGNAL ;
    PORT
      LAYER M4 ;
        RECT  0 26.928 0.084 26.952 ;
    END
  END o[5]
  PIN o[60]
    DIRECTION OUTPUT ;
    USE SIGNAL ;
    PORT
      LAYER M4 ;
        RECT  0 22.992 0.084 23.016 ;
    END
  END o[60]
  PIN o[61]
    DIRECTION OUTPUT ;
    USE SIGNAL ;
    PORT
      LAYER M4 ;
        RECT  0 23.088 0.084 23.112 ;
    END
  END o[61]
  PIN o[62]
    DIRECTION OUTPUT ;
    USE SIGNAL ;
    PORT
      LAYER M4 ;
        RECT  0 23.184 0.084 23.208 ;
    END
  END o[62]
  PIN o[63]
    DIRECTION OUTPUT ;
    USE SIGNAL ;
    PORT
      LAYER M4 ;
        RECT  0 23.28 0.084 23.304 ;
    END
  END o[63]
  PIN o[64]
    DIRECTION OUTPUT ;
    USE SIGNAL ;
    PORT
      LAYER M4 ;
        RECT  0 17.232 0.084 17.256 ;
    END
  END o[64]
  PIN o[65]
    DIRECTION OUTPUT ;
    USE SIGNAL ;
    PORT
      LAYER M4 ;
        RECT  0 17.328 0.084 17.352 ;
    END
  END o[65]
  PIN o[66]
    DIRECTION OUTPUT ;
    USE SIGNAL ;
    PORT
      LAYER M4 ;
        RECT  0 17.424 0.084 17.448 ;
    END
  END o[66]
  PIN o[67]
    DIRECTION OUTPUT ;
    USE SIGNAL ;
    PORT
      LAYER M4 ;
        RECT  0 17.52 0.084 17.544 ;
    END
  END o[67]
  PIN o[68]
    DIRECTION OUTPUT ;
    USE SIGNAL ;
    PORT
      LAYER M4 ;
        RECT  0 17.616 0.084 17.64 ;
    END
  END o[68]
  PIN o[69]
    DIRECTION OUTPUT ;
    USE SIGNAL ;
    PORT
      LAYER M4 ;
        RECT  0 17.712 0.084 17.736 ;
    END
  END o[69]
  PIN o[6]
    DIRECTION OUTPUT ;
    USE SIGNAL ;
    PORT
      LAYER M4 ;
        RECT  0 27.024 0.084 27.048 ;
    END
  END o[6]
  PIN o[70]
    DIRECTION OUTPUT ;
    USE SIGNAL ;
    PORT
      LAYER M4 ;
        RECT  0 17.808 0.084 17.832 ;
    END
  END o[70]
  PIN o[71]
    DIRECTION OUTPUT ;
    USE SIGNAL ;
    PORT
      LAYER M4 ;
        RECT  0 17.904 0.084 17.928 ;
    END
  END o[71]
  PIN o[72]
    DIRECTION OUTPUT ;
    USE SIGNAL ;
    PORT
      LAYER M4 ;
        RECT  0 18 0.084 18.024 ;
    END
  END o[72]
  PIN o[73]
    DIRECTION OUTPUT ;
    USE SIGNAL ;
    PORT
      LAYER M4 ;
        RECT  0 18.096 0.084 18.12 ;
    END
  END o[73]
  PIN o[74]
    DIRECTION OUTPUT ;
    USE SIGNAL ;
    PORT
      LAYER M4 ;
        RECT  0 18.192 0.084 18.216 ;
    END
  END o[74]
  PIN o[75]
    DIRECTION OUTPUT ;
    USE SIGNAL ;
    PORT
      LAYER M4 ;
        RECT  0 18.288 0.084 18.312 ;
    END
  END o[75]
  PIN o[76]
    DIRECTION OUTPUT ;
    USE SIGNAL ;
    PORT
      LAYER M4 ;
        RECT  0 18.384 0.084 18.408 ;
    END
  END o[76]
  PIN o[77]
    DIRECTION OUTPUT ;
    USE SIGNAL ;
    PORT
      LAYER M4 ;
        RECT  0 18.48 0.084 18.504 ;
    END
  END o[77]
  PIN o[78]
    DIRECTION OUTPUT ;
    USE SIGNAL ;
    PORT
      LAYER M4 ;
        RECT  0 18.576 0.084 18.6 ;
    END
  END o[78]
  PIN o[79]
    DIRECTION OUTPUT ;
    USE SIGNAL ;
    PORT
      LAYER M4 ;
        RECT  0 18.672 0.084 18.696 ;
    END
  END o[79]
  PIN o[7]
    DIRECTION OUTPUT ;
    USE SIGNAL ;
    PORT
      LAYER M4 ;
        RECT  0 27.12 0.084 27.144 ;
    END
  END o[7]
  PIN o[80]
    DIRECTION OUTPUT ;
    USE SIGNAL ;
    PORT
      LAYER M4 ;
        RECT  0 18.768 0.084 18.792 ;
    END
  END o[80]
  PIN o[81]
    DIRECTION OUTPUT ;
    USE SIGNAL ;
    PORT
      LAYER M4 ;
        RECT  0 18.864 0.084 18.888 ;
    END
  END o[81]
  PIN o[82]
    DIRECTION OUTPUT ;
    USE SIGNAL ;
    PORT
      LAYER M4 ;
        RECT  0 18.96 0.084 18.984 ;
    END
  END o[82]
  PIN o[83]
    DIRECTION OUTPUT ;
    USE SIGNAL ;
    PORT
      LAYER M4 ;
        RECT  0 19.056 0.084 19.08 ;
    END
  END o[83]
  PIN o[84]
    DIRECTION OUTPUT ;
    USE SIGNAL ;
    PORT
      LAYER M4 ;
        RECT  0 19.152 0.084 19.176 ;
    END
  END o[84]
  PIN o[85]
    DIRECTION OUTPUT ;
    USE SIGNAL ;
    PORT
      LAYER M4 ;
        RECT  0 19.248 0.084 19.272 ;
    END
  END o[85]
  PIN o[86]
    DIRECTION OUTPUT ;
    USE SIGNAL ;
    PORT
      LAYER M4 ;
        RECT  0 19.344 0.084 19.368 ;
    END
  END o[86]
  PIN o[87]
    DIRECTION OUTPUT ;
    USE SIGNAL ;
    PORT
      LAYER M4 ;
        RECT  0 19.44 0.084 19.464 ;
    END
  END o[87]
  PIN o[88]
    DIRECTION OUTPUT ;
    USE SIGNAL ;
    PORT
      LAYER M4 ;
        RECT  0 19.536 0.084 19.56 ;
    END
  END o[88]
  PIN o[89]
    DIRECTION OUTPUT ;
    USE SIGNAL ;
    PORT
      LAYER M4 ;
        RECT  0 19.632 0.084 19.656 ;
    END
  END o[89]
  PIN o[8]
    DIRECTION OUTPUT ;
    USE SIGNAL ;
    PORT
      LAYER M4 ;
        RECT  0 27.216 0.084 27.24 ;
    END
  END o[8]
  PIN o[90]
    DIRECTION OUTPUT ;
    USE SIGNAL ;
    PORT
      LAYER M4 ;
        RECT  0 19.728 0.084 19.752 ;
    END
  END o[90]
  PIN o[91]
    DIRECTION OUTPUT ;
    USE SIGNAL ;
    PORT
      LAYER M4 ;
        RECT  0 19.824 0.084 19.848 ;
    END
  END o[91]
  PIN o[92]
    DIRECTION OUTPUT ;
    USE SIGNAL ;
    PORT
      LAYER M4 ;
        RECT  0 19.92 0.084 19.944 ;
    END
  END o[92]
  PIN o[93]
    DIRECTION OUTPUT ;
    USE SIGNAL ;
    PORT
      LAYER M4 ;
        RECT  0 20.016 0.084 20.04 ;
    END
  END o[93]
  PIN o[94]
    DIRECTION OUTPUT ;
    USE SIGNAL ;
    PORT
      LAYER M4 ;
        RECT  0 20.112 0.084 20.136 ;
    END
  END o[94]
  PIN o[95]
    DIRECTION OUTPUT ;
    USE SIGNAL ;
    PORT
      LAYER M4 ;
        RECT  0 20.208 0.084 20.232 ;
    END
  END o[95]
  PIN o[96]
    DIRECTION OUTPUT ;
    USE SIGNAL ;
    PORT
      LAYER M4 ;
        RECT  0 14.16 0.084 14.184 ;
    END
  END o[96]
  PIN o[97]
    DIRECTION OUTPUT ;
    USE SIGNAL ;
    PORT
      LAYER M4 ;
        RECT  0 14.256 0.084 14.28 ;
    END
  END o[97]
  PIN o[98]
    DIRECTION OUTPUT ;
    USE SIGNAL ;
    PORT
      LAYER M4 ;
        RECT  0 14.352 0.084 14.376 ;
    END
  END o[98]
  PIN o[99]
    DIRECTION OUTPUT ;
    USE SIGNAL ;
    PORT
      LAYER M4 ;
        RECT  0 14.448 0.084 14.472 ;
    END
  END o[99]
  PIN o[9]
    DIRECTION OUTPUT ;
    USE SIGNAL ;
    PORT
      LAYER M4 ;
        RECT  0 27.312 0.084 27.336 ;
    END
  END o[9]
  PIN rs
    DIRECTION INPUT ;
    USE SIGNAL ;
    PORT
      LAYER M5 ;
        RECT  8.592 30.156 8.616 30.24 ;
    END
  END rs
  PIN VDD
    DIRECTION INOUT ;
    USE POWER ;
    PORT
      LAYER M5 ;
        RECT  18.792 2.151 18.912 28.089 ;
        RECT  13.392 2.151 13.512 28.089 ;
        RECT  7.992 2.151 8.112 28.089 ;
        RECT  2.592 2.151 2.712 28.089 ;
    END
  END VDD
  PIN VSS
    DIRECTION INOUT ;
    USE GROUND ;
    PORT
      LAYER M5 ;
        RECT  18.6 2.137 18.72 28.103 ;
        RECT  13.2 2.137 13.32 28.103 ;
        RECT  7.8 2.137 7.92 28.103 ;
        RECT  2.4 2.137 2.52 28.103 ;
    END
  END VSS
  OBS
    LAYER RVTN ;
     RECT  2.16 2.16 21.6 2.295 ;
     RECT  2.16 2.565 21.6 2.835 ;
     RECT  2.16 3.105 21.6 3.375 ;
     RECT  2.16 3.645 21.6 3.915 ;
     RECT  2.16 4.185 21.6 4.455 ;
     RECT  2.16 4.725 21.6 4.995 ;
     RECT  2.16 5.265 21.6 5.535 ;
     RECT  2.16 5.805 21.6 6.075 ;
     RECT  2.16 6.345 21.6 6.615 ;
     RECT  2.16 6.885 21.6 7.155 ;
     RECT  2.16 7.425 21.6 7.695 ;
     RECT  2.16 7.965 21.6 8.235 ;
     RECT  2.16 8.505 21.6 8.775 ;
     RECT  2.16 9.045 21.6 9.315 ;
     RECT  2.16 9.585 21.6 9.855 ;
     RECT  2.16 10.125 21.6 10.395 ;
     RECT  2.16 10.665 21.6 10.935 ;
     RECT  2.16 11.205 21.6 11.475 ;
     RECT  2.16 11.745 21.6 12.015 ;
     RECT  2.16 12.285 21.6 12.555 ;
     RECT  2.16 12.825 21.6 13.095 ;
     RECT  2.16 13.365 21.6 13.635 ;
     RECT  2.16 13.905 21.6 14.175 ;
     RECT  2.16 14.445 21.6 14.715 ;
     RECT  2.16 14.985 21.6 15.255 ;
     RECT  2.16 15.525 21.6 15.795 ;
     RECT  2.16 16.065 21.6 16.335 ;
     RECT  2.16 16.605 21.6 16.875 ;
     RECT  2.16 17.145 21.6 17.415 ;
     RECT  2.16 17.685 21.6 17.955 ;
     RECT  2.16 18.225 21.6 18.495 ;
     RECT  2.16 18.765 21.6 19.035 ;
     RECT  2.16 19.305 21.6 19.575 ;
     RECT  2.16 19.845 21.6 20.115 ;
     RECT  2.16 20.385 21.6 20.655 ;
     RECT  2.16 20.925 21.6 21.195 ;
     RECT  2.16 21.465 21.6 21.735 ;
     RECT  2.16 22.005 21.6 22.275 ;
     RECT  2.16 22.545 21.6 22.815 ;
     RECT  2.16 23.085 21.6 23.355 ;
     RECT  2.16 23.625 21.6 23.895 ;
     RECT  2.16 24.165 21.6 24.435 ;
     RECT  2.16 24.705 21.6 24.975 ;
     RECT  2.16 25.245 21.6 25.515 ;
     RECT  2.16 25.785 21.6 26.055 ;
     RECT  2.16 26.325 21.6 26.595 ;
     RECT  2.16 26.865 21.6 27.135 ;
     RECT  2.16 27.405 21.6 27.675 ;
     RECT  2.16 27.945 21.6 28.08 ;
    LAYER RVTP ;
     RECT  2.16 2.295 21.6 2.565 ;
     RECT  2.16 2.835 21.6 3.105 ;
     RECT  2.16 3.375 21.6 3.645 ;
     RECT  2.16 3.915 21.6 4.185 ;
     RECT  2.16 4.455 21.6 4.725 ;
     RECT  2.16 4.995 21.6 5.265 ;
     RECT  2.16 5.535 21.6 5.805 ;
     RECT  2.16 6.075 21.6 6.345 ;
     RECT  2.16 6.615 21.6 6.885 ;
     RECT  2.16 7.155 21.6 7.425 ;
     RECT  2.16 7.695 21.6 7.965 ;
     RECT  2.16 8.235 21.6 8.505 ;
     RECT  2.16 8.775 21.6 9.045 ;
     RECT  2.16 9.315 21.6 9.585 ;
     RECT  2.16 9.855 21.6 10.125 ;
     RECT  2.16 10.395 21.6 10.665 ;
     RECT  2.16 10.935 21.6 11.205 ;
     RECT  2.16 11.475 21.6 11.745 ;
     RECT  2.16 12.015 21.6 12.285 ;
     RECT  2.16 12.555 21.6 12.825 ;
     RECT  2.16 13.095 21.6 13.365 ;
     RECT  2.16 13.635 21.6 13.905 ;
     RECT  2.16 14.175 21.6 14.445 ;
     RECT  2.16 14.715 21.6 14.985 ;
     RECT  2.16 15.255 21.6 15.525 ;
     RECT  2.16 15.795 21.6 16.065 ;
     RECT  2.16 16.335 21.6 16.605 ;
     RECT  2.16 16.875 21.6 17.145 ;
     RECT  2.16 17.415 21.6 17.685 ;
     RECT  2.16 17.955 21.6 18.225 ;
     RECT  2.16 18.495 21.6 18.765 ;
     RECT  2.16 19.035 21.6 19.305 ;
     RECT  2.16 19.575 21.6 19.845 ;
     RECT  2.16 20.115 21.6 20.385 ;
     RECT  2.16 20.655 21.6 20.925 ;
     RECT  2.16 21.195 21.6 21.465 ;
     RECT  2.16 21.735 21.6 22.005 ;
     RECT  2.16 22.275 21.6 22.545 ;
     RECT  2.16 22.815 21.6 23.085 ;
     RECT  2.16 23.355 21.6 23.625 ;
     RECT  2.16 23.895 21.6 24.165 ;
     RECT  2.16 24.435 21.6 24.705 ;
     RECT  2.16 24.975 21.6 25.245 ;
     RECT  2.16 25.515 21.6 25.785 ;
     RECT  2.16 26.055 21.6 26.325 ;
     RECT  2.16 26.595 21.6 26.865 ;
     RECT  2.16 27.135 21.6 27.405 ;
     RECT  2.16 27.675 21.6 27.945 ;
    LAYER M1 ;
     RECT  2.16 2.151 21.6 28.089 ;
    LAYER M2 ;
     RECT  0.031 6.858 0.067 6.948 ;
     RECT  0.031 16.542 0.067 17.019 ;
     RECT  0.067 6.12 0.131 6.948 ;
     RECT  0.031 5.076 0.139 5.094 ;
     RECT  0.131 6.12 0.139 6.876 ;
     RECT  0.103 8.712 0.139 8.73 ;
     RECT  0.103 9.936 0.139 9.954 ;
     RECT  0.103 21.402 0.139 21.42 ;
     RECT  0.103 25.911 0.139 25.929 ;
     RECT  0.103 13.914 0.175 13.932 ;
     RECT  0.103 7.902 0.203 7.92 ;
     RECT  0.139 8.712 0.203 9.144 ;
     RECT  0.103 13.068 0.203 13.086 ;
     RECT  0.175 13.914 0.203 14.094 ;
     RECT  0.139 25.866 0.203 25.929 ;
     RECT  0.103 27.612 0.203 27.63 ;
     RECT  0.203 9.126 0.239 9.144 ;
     RECT  0.103 14.994 0.239 15.012 ;
     RECT  0.203 25.866 0.239 25.884 ;
     RECT  0.139 4.662 0.311 6.876 ;
     RECT  0.311 6.588 0.347 6.876 ;
     RECT  0.311 4.662 0.383 5.76 ;
     RECT  0.067 16.542 0.391 17.172 ;
     RECT  0.383 4.77 0.419 5.76 ;
     RECT  0.391 16.506 0.463 17.172 ;
     RECT  0.031 18.234 0.463 18.252 ;
     RECT  0.103 19.62 0.463 19.638 ;
     RECT  0.139 21.402 0.463 21.834 ;
     RECT  0.283 12.456 0.499 12.924 ;
     RECT  0.463 16.506 0.499 17.244 ;
     RECT  0.463 18.126 0.499 18.252 ;
     RECT  0.463 19.206 0.499 19.638 ;
     RECT  0.463 23.526 0.499 23.544 ;
     RECT  0.499 15.768 0.535 17.244 ;
     RECT  0.499 18.036 0.535 20.304 ;
     RECT  0.463 21.402 0.535 21.996 ;
     RECT  0.499 22.896 0.535 24.264 ;
     RECT  0.103 26.766 0.535 26.784 ;
     RECT  0.139 9.936 0.607 10.458 ;
     RECT  0.535 15.768 0.859 20.412 ;
     RECT  0.535 21.402 0.859 22.032 ;
     RECT  0.203 14.076 1.003 14.094 ;
     RECT  0.607 9.396 1.039 10.458 ;
     RECT  1.003 14.076 1.103 14.544 ;
     RECT  0.535 22.896 1.399 24.894 ;
     RECT  0.535 26.766 1.399 27.234 ;
     RECT  0.859 15.768 1.435 22.032 ;
     RECT  1.399 22.86 1.435 24.894 ;
     RECT  0.499 12.222 1.579 12.924 ;
     RECT  1.579 12.222 1.687 13.158 ;
     RECT  1.103 14.076 1.687 14.094 ;
     RECT  0.347 6.588 1.723 6.804 ;
     RECT  0.419 4.806 2.083 5.76 ;
     RECT  1.435 15.768 2.083 24.894 ;
     RECT  2.083 4.086 2.16 5.76 ;
     RECT  1.723 6.588 2.16 7.074 ;
     RECT  1.039 9.396 2.16 10.692 ;
     RECT  1.687 12.222 2.16 14.094 ;
     RECT  2.083 15.498 2.16 24.894 ;
     RECT  0.895 25.686 2.16 25.704 ;
     RECT  1.399 26.604 2.16 27.234 ;
     RECT  2.16 2.151 4.459 28.089 ;
     RECT  4.459 1.656 13.063 28.089 ;
     RECT  13.063 1.611 19.427 28.089 ;
     RECT  19.427 1.656 20.327 28.089 ;
     RECT  20.327 1.692 21.407 28.089 ;
     RECT  21.407 1.836 21.6 28.089 ;
     RECT  21.6 1.836 21.695 19.098 ;
     RECT  21.6 20.088 21.695 27.234 ;
     RECT  21.695 1.836 21.731 10.152 ;
     RECT  21.695 10.908 21.767 19.098 ;
     RECT  21.731 1.836 22.163 3.636 ;
     RECT  21.731 4.428 22.163 10.116 ;
     RECT  22.163 1.836 22.235 2.052 ;
     RECT  21.767 10.908 22.235 14.544 ;
     RECT  21.695 20.16 22.235 27.234 ;
     RECT  21.767 15.498 22.271 19.098 ;
     RECT  22.235 20.16 22.271 22.068 ;
     RECT  22.235 12.798 22.307 14.544 ;
     RECT  22.163 4.968 22.343 10.116 ;
     RECT  22.235 23.058 22.379 26.658 ;
     RECT  22.343 6.12 22.739 10.116 ;
     RECT  22.235 10.908 22.739 11.844 ;
     RECT  22.307 12.798 22.739 12.816 ;
     RECT  22.307 13.608 22.739 14.544 ;
     RECT  22.271 15.498 22.739 19.062 ;
     RECT  22.271 20.16 22.739 21.996 ;
     RECT  22.739 20.16 22.783 21.798 ;
     RECT  22.235 1.836 22.811 2.016 ;
     RECT  22.739 11.178 22.811 11.772 ;
     RECT  22.739 15.498 22.811 16.866 ;
     RECT  22.379 23.058 22.811 25.344 ;
     RECT  22.739 6.12 22.847 9.918 ;
     RECT  22.811 11.484 22.847 11.772 ;
     RECT  22.739 17.73 22.847 19.062 ;
     RECT  22.783 20.052 22.847 21.798 ;
     RECT  22.847 6.696 22.883 7.488 ;
     RECT  22.163 3.042 22.891 3.366 ;
     RECT  22.891 2.961 22.991 3.366 ;
     RECT  22.343 4.968 23.431 5.256 ;
     RECT  22.811 15.498 23.539 16.794 ;
     RECT  22.847 17.73 23.539 18.72 ;
     RECT  23.431 4.851 23.567 5.256 ;
     RECT  22.811 1.836 23.575 1.854 ;
     RECT  22.883 6.696 23.575 6.759 ;
     RECT  22.739 14.22 23.575 14.544 ;
     RECT  23.539 15.498 23.575 18.72 ;
     RECT  22.847 21.78 23.575 21.798 ;
     RECT  22.811 23.058 23.575 25.236 ;
     RECT  23.575 6.012 23.639 6.759 ;
     RECT  22.847 9.666 23.639 9.918 ;
     RECT  22.379 26.1 23.639 26.658 ;
     RECT  23.575 1.836 23.675 2.484 ;
     RECT  22.991 3.348 23.675 3.366 ;
     RECT  23.567 5.238 23.675 5.256 ;
     RECT  23.639 6.012 23.675 6.372 ;
     RECT  23.639 9.666 23.675 9.846 ;
     RECT  23.575 14.22 23.675 18.72 ;
     RECT  22.847 20.052 23.675 20.07 ;
     RECT  23.575 21.78 23.675 25.236 ;
     RECT  23.639 26.136 23.675 26.658 ;
    LAYER M3 ;
     RECT  13.788 0.811 13.806 0.907 ;
     RECT  13.608 0.907 13.806 1.003 ;
     RECT  20.448 0.715 20.466 1.099 ;
     RECT  22.14 1.195 22.158 1.483 ;
     RECT  13.608 1.003 14.454 1.606 ;
     RECT  22.068 1.483 22.158 1.675 ;
     RECT  4.464 1.651 4.482 1.687 ;
     RECT  22.068 1.675 22.806 1.687 ;
     RECT  20.268 1.099 20.466 1.771 ;
     RECT  21.384 1.687 22.806 1.771 ;
     RECT  15.768 1.795 15.786 1.819 ;
     RECT  13.068 1.606 14.454 1.831 ;
     RECT  15.408 1.819 15.786 1.831 ;
     RECT  20.268 1.771 22.806 1.831 ;
     RECT  19.404 1.606 19.422 1.876 ;
     RECT  20.232 1.831 22.806 1.876 ;
     RECT  12.852 1.831 14.454 1.921 ;
     RECT  15.408 1.831 16.506 1.921 ;
     RECT  12.852 1.921 16.506 1.957 ;
     RECT  17.388 1.915 17.406 1.957 ;
     RECT  12.636 1.957 17.406 2.011 ;
     RECT  19.404 1.876 22.806 2.011 ;
     RECT  12.528 2.011 17.406 2.029 ;
     RECT  12.528 2.029 17.55 2.059 ;
     RECT  18.756 2.011 22.806 2.065 ;
     RECT  23.652 1.579 23.67 2.299 ;
     RECT  11.952 2.059 17.55 2.335 ;
     RECT  18.324 2.065 22.806 2.335 ;
     RECT  6.228 2.251 6.246 2.371 ;
     RECT  2.415 2.143 2.505 2.413 ;
     RECT  7.815 2.143 7.905 2.413 ;
     RECT  4.464 1.687 4.698 2.569 ;
     RECT  6.228 2.371 6.858 2.569 ;
     RECT  11.952 2.335 22.806 2.597 ;
     RECT  11.988 2.597 22.806 2.635 ;
     RECT  23.544 2.299 23.67 2.635 ;
     RECT  3.816 2.569 4.698 2.641 ;
     RECT  10.656 1.915 10.674 2.731 ;
     RECT  11.988 2.635 23.67 2.759 ;
     RECT  6.228 2.569 6.93 2.767 ;
     RECT  7.815 2.413 8.097 2.767 ;
     RECT  9.396 2.461 9.414 2.839 ;
     RECT  9.252 2.839 9.414 2.875 ;
     RECT  3.528 2.641 4.698 2.911 ;
     RECT  6.228 2.767 8.097 2.911 ;
     RECT  9.036 2.875 9.414 2.911 ;
     RECT  3.528 2.911 5.238 3.001 ;
     RECT  6.228 2.911 9.594 3.001 ;
     RECT  10.656 2.731 11.034 3.067 ;
     RECT  10.62 3.067 11.034 3.073 ;
     RECT  11.988 2.759 21.186 3.101 ;
     RECT  10.584 3.073 11.034 3.109 ;
     RECT  22.068 2.759 23.67 3.173 ;
     RECT  3.456 3.001 9.666 3.181 ;
     RECT  22.068 3.173 22.266 3.209 ;
     RECT  2.415 2.413 2.697 3.307 ;
     RECT  3.456 3.181 9.774 3.307 ;
     RECT  23.58 3.173 23.67 3.371 ;
     RECT  11.988 3.101 20.43 3.389 ;
     RECT  12.528 3.389 20.43 3.479 ;
     RECT  0.144 3.211 0.162 3.499 ;
     RECT  22.068 3.209 22.158 3.499 ;
     RECT  2.415 3.307 9.774 3.613 ;
     RECT  10.584 3.109 11.07 3.613 ;
     RECT  0.144 3.499 0.342 3.691 ;
     RECT  2.415 3.613 11.07 3.739 ;
     RECT  12.564 3.479 20.43 3.773 ;
     RECT  21.708 3.499 22.158 3.883 ;
     RECT  21.672 3.883 22.158 3.983 ;
     RECT  2.304 3.739 11.07 3.991 ;
     RECT  2.304 3.991 11.574 4.072 ;
     RECT  2.088 4.072 11.574 4.189 ;
     RECT  2.088 4.189 11.718 4.267 ;
     RECT  1.728 4.267 11.718 4.531 ;
     RECT  12.564 3.773 20.394 4.531 ;
     RECT  21.744 3.983 22.158 4.555 ;
     RECT  0.108 3.691 0.342 4.657 ;
     RECT  0.108 4.657 0.378 4.765 ;
     RECT  21.744 4.555 22.734 4.795 ;
     RECT  23.58 3.371 23.598 4.795 ;
     RECT  0.108 4.765 0.414 4.801 ;
     RECT  1.728 4.531 20.394 4.801 ;
     RECT  21.744 4.795 23.598 4.801 ;
     RECT  1.728 4.801 23.598 4.874 ;
     RECT  23.544 4.874 23.598 4.877 ;
     RECT  1.728 4.874 22.734 4.919 ;
     RECT  21.672 4.919 22.734 4.991 ;
     RECT  23.58 4.877 23.598 5.021 ;
     RECT  0.108 4.801 0.954 5.071 ;
     RECT  23.652 5.131 23.67 5.261 ;
     RECT  0.036 5.071 0.954 5.323 ;
     RECT  1.728 4.919 20.394 5.323 ;
     RECT  21.672 4.991 22.338 5.333 ;
     RECT  21.78 5.333 22.338 5.603 ;
     RECT  23.58 5.755 23.598 5.995 ;
     RECT  0.036 5.323 20.394 6.091 ;
     RECT  22.14 5.603 22.338 6.115 ;
     RECT  0.036 6.091 20.466 6.232 ;
     RECT  22.14 6.115 22.842 6.413 ;
     RECT  23.58 5.995 23.67 6.413 ;
     RECT  0.036 6.232 21.006 6.475 ;
     RECT  22.788 6.413 22.842 6.667 ;
     RECT  23.58 6.413 23.634 6.667 ;
     RECT  0.036 6.475 21.618 6.719 ;
     RECT  22.788 6.667 23.634 6.797 ;
     RECT  0.036 6.719 20.718 6.845 ;
     RECT  21.564 6.719 21.618 7.151 ;
     RECT  21.636 7.231 21.654 7.339 ;
     RECT  22.788 6.797 22.878 7.339 ;
     RECT  0.036 6.845 20.466 7.349 ;
     RECT  21.636 7.339 22.878 7.949 ;
     RECT  0.036 7.349 20.43 8.311 ;
     RECT  21.636 7.949 22.842 8.395 ;
     RECT  0.036 8.311 20.466 8.545 ;
     RECT  21.6 8.395 22.842 8.545 ;
     RECT  23.58 8.539 23.598 8.717 ;
     RECT  0.036 8.545 22.842 8.731 ;
     RECT  0.036 8.731 23.526 8.969 ;
     RECT  21.78 8.969 23.526 9.005 ;
     RECT  21.78 9.005 22.842 9.113 ;
     RECT  22.248 9.113 22.842 9.347 ;
     RECT  22.716 9.347 22.842 9.739 ;
     RECT  23.616 9.451 23.67 9.739 ;
     RECT  22.716 9.739 23.67 9.869 ;
     RECT  23.508 9.869 23.634 9.923 ;
     RECT  0.036 8.969 20.826 10.027 ;
     RECT  21.708 9.931 21.726 10.027 ;
     RECT  0.036 10.027 21.726 10.121 ;
     RECT  0.036 10.121 20.466 10.319 ;
     RECT  0.036 10.319 20.394 10.349 ;
     RECT  23.508 9.923 23.598 10.541 ;
     RECT  23.508 10.541 23.526 10.637 ;
     RECT  21.564 10.121 21.726 10.661 ;
     RECT  22.716 9.869 22.734 10.699 ;
     RECT  22.248 10.699 22.734 11.173 ;
     RECT  0.036 10.349 20.358 11.281 ;
     RECT  0.036 11.281 20.394 11.371 ;
     RECT  22.248 11.173 22.806 11.479 ;
     RECT  0.036 11.371 21.078 11.515 ;
     RECT  0.036 11.515 21.15 11.939 ;
     RECT  0.036 11.939 20.898 11.975 ;
     RECT  22.248 11.479 22.842 11.981 ;
     RECT  22.248 11.981 22.734 12.139 ;
     RECT  21.636 12.139 22.734 12.281 ;
     RECT  21.636 12.281 21.762 12.551 ;
     RECT  21.672 12.551 21.762 12.557 ;
     RECT  0.036 11.975 20.79 12.749 ;
     RECT  23.58 12.571 23.598 12.811 ;
     RECT  23.472 12.811 23.598 12.941 ;
     RECT  21.744 12.557 21.762 13.063 ;
     RECT  22.716 12.281 22.734 13.063 ;
     RECT  21.744 13.063 22.734 13.325 ;
     RECT  20.772 12.749 20.79 13.405 ;
     RECT  21.744 13.325 21.87 13.405 ;
     RECT  0.036 12.749 20.034 13.531 ;
     RECT  20.772 13.405 21.87 13.531 ;
     RECT  22.716 13.325 22.734 13.901 ;
     RECT  0.036 13.531 21.87 13.973 ;
     RECT  23.58 12.941 23.598 14.155 ;
     RECT  0.036 13.973 21.762 14.207 ;
     RECT  23.58 14.155 23.67 14.251 ;
     RECT  23.472 14.251 23.67 14.341 ;
     RECT  22.788 14.341 23.67 14.441 ;
     RECT  0.036 14.207 20.79 14.639 ;
     RECT  23.472 14.441 23.67 14.765 ;
     RECT  21.636 14.207 21.762 15.019 ;
     RECT  21.564 15.019 21.762 15.251 ;
     RECT  0.036 14.639 20.574 15.359 ;
     RECT  22.212 15.307 22.266 15.787 ;
     RECT  23.58 14.765 23.67 15.899 ;
     RECT  22.212 15.787 22.734 16.141 ;
     RECT  22.212 16.141 22.842 16.171 ;
     RECT  21.672 16.171 22.842 16.301 ;
     RECT  21.672 16.301 22.806 16.331 ;
     RECT  0.036 15.359 20.466 16.501 ;
     RECT  22.716 16.331 22.806 16.601 ;
     RECT  21.672 16.331 21.69 16.673 ;
     RECT  0.036 16.501 20.754 16.747 ;
     RECT  21.528 16.681 21.654 16.747 ;
     RECT  23.652 15.899 23.67 16.795 ;
     RECT  22.788 16.601 22.806 16.871 ;
     RECT  0.036 16.747 21.654 17.105 ;
     RECT  0.036 17.105 21.402 17.339 ;
     RECT  0.036 17.339 21.186 17.411 ;
     RECT  23.58 16.795 23.67 17.467 ;
     RECT  23.544 17.467 23.67 17.519 ;
     RECT  23.616 17.519 23.67 17.549 ;
     RECT  22.716 17.323 22.734 17.725 ;
     RECT  22.716 17.725 22.878 17.837 ;
     RECT  0.036 17.411 20.862 18.257 ;
     RECT  22.716 17.837 22.842 18.379 ;
     RECT  0.18 18.257 20.862 18.391 ;
     RECT  21.888 18.475 21.906 18.563 ;
     RECT  23.652 17.549 23.67 18.725 ;
     RECT  0.18 18.391 21.078 18.841 ;
     RECT  22.68 18.379 22.842 18.859 ;
     RECT  0.18 18.841 21.114 18.959 ;
     RECT  21.096 18.959 21.114 18.989 ;
     RECT  22.248 18.859 22.842 19.067 ;
     RECT  22.248 19.067 22.266 19.103 ;
     RECT  0.18 18.959 20.322 19.139 ;
     RECT  0.18 19.139 20.286 19.301 ;
     RECT  0.18 19.301 17.298 19.435 ;
     RECT  0.144 19.435 17.298 19.612 ;
     RECT  0.108 19.612 17.298 19.757 ;
     RECT  18.108 19.301 20.286 19.867 ;
     RECT  21.132 19.471 21.15 19.885 ;
     RECT  21.096 19.885 21.15 20.011 ;
     RECT  18.108 19.867 20.322 20.047 ;
     RECT  21.06 20.011 21.15 20.047 ;
     RECT  23.652 20.011 23.67 20.075 ;
     RECT  18.108 20.047 21.15 20.083 ;
     RECT  18.108 20.083 21.69 20.141 ;
     RECT  0.18 19.757 17.298 20.155 ;
     RECT  18.108 20.141 20.538 20.155 ;
     RECT  0.18 20.155 20.538 20.237 ;
     RECT  21.636 20.141 21.69 20.395 ;
     RECT  22.788 20.047 22.806 20.395 ;
     RECT  21.636 20.395 22.806 20.525 ;
     RECT  22.14 20.525 22.806 20.731 ;
     RECT  22.14 20.731 22.842 20.921 ;
     RECT  0.18 20.237 20.466 20.971 ;
     RECT  0.18 20.971 21.078 21.211 ;
     RECT  0.144 21.211 21.078 21.388 ;
     RECT  22.248 20.921 22.842 21.485 ;
     RECT  0.108 21.388 21.078 21.581 ;
     RECT  0.144 21.581 21.078 21.643 ;
     RECT  0.144 21.643 21.114 21.725 ;
     RECT  0.144 21.725 20.322 21.869 ;
     RECT  22.248 21.485 22.734 22.001 ;
     RECT  22.248 22.001 22.266 22.073 ;
     RECT  23.652 21.547 23.67 22.075 ;
     RECT  21.06 21.725 21.114 22.219 ;
     RECT  0.18 21.869 20.322 22.585 ;
     RECT  21.06 22.219 22.23 22.585 ;
     RECT  0.18 22.585 22.23 22.739 ;
     RECT  0.18 22.739 20.79 22.781 ;
     RECT  23.58 22.075 23.67 22.919 ;
     RECT  21.672 22.739 22.23 23.309 ;
     RECT  23.616 22.919 23.67 23.351 ;
     RECT  0.18 22.781 20.61 23.501 ;
     RECT  0.468 23.501 20.61 23.819 ;
     RECT  22.248 23.371 22.266 23.851 ;
     RECT  0.468 23.819 20.394 23.963 ;
     RECT  0.468 23.963 9.666 23.999 ;
     RECT  2.016 23.999 9.666 24.173 ;
     RECT  0.468 23.999 0.918 24.269 ;
     RECT  2.016 24.173 9.594 24.431 ;
     RECT  22.248 23.851 22.806 24.511 ;
     RECT  23.652 23.351 23.67 24.523 ;
     RECT  10.476 23.963 20.394 24.601 ;
     RECT  23.616 24.523 23.67 24.737 ;
     RECT  10.476 24.601 20.43 24.859 ;
     RECT  10.476 24.859 20.466 24.899 ;
     RECT  0.504 24.269 0.918 24.941 ;
     RECT  10.476 24.899 20.43 24.989 ;
     RECT  10.476 24.989 20.322 25.229 ;
     RECT  21.672 24.511 22.806 25.249 ;
     RECT  21.312 25.249 22.806 25.349 ;
     RECT  21.312 25.349 22.374 25.439 ;
     RECT  0.54 24.941 0.918 25.675 ;
     RECT  0.324 25.675 0.918 25.709 ;
     RECT  0.324 25.709 0.342 25.805 ;
     RECT  21.636 25.439 22.374 25.817 ;
     RECT  0.216 25.819 0.234 25.861 ;
     RECT  11.844 25.229 20.322 25.861 ;
     RECT  0.144 25.861 0.234 25.889 ;
     RECT  0.144 25.889 0.198 25.9 ;
     RECT  23.652 24.737 23.67 25.963 ;
     RECT  2.304 24.431 9.594 26.023 ;
     RECT  10.476 25.229 11.07 26.023 ;
     RECT  22.176 25.817 22.374 26.155 ;
     RECT  22.176 26.155 22.734 26.321 ;
     RECT  11.844 25.861 20.394 26.347 ;
     RECT  22.176 26.321 22.266 26.393 ;
     RECT  2.304 26.023 11.07 26.477 ;
     RECT  23.616 25.963 23.67 26.587 ;
     RECT  23.58 26.587 23.67 26.663 ;
     RECT  23.58 26.663 23.598 26.765 ;
     RECT  0.108 25.9 0.198 26.779 ;
     RECT  11.844 26.347 20.826 26.789 ;
     RECT  22.176 26.393 22.23 26.827 ;
     RECT  21.744 26.827 22.23 26.923 ;
     RECT  2.415 26.477 11.07 26.933 ;
     RECT  11.844 26.789 13.497 26.933 ;
     RECT  14.256 26.789 19.926 27.059 ;
     RECT  14.256 27.059 19.854 27.095 ;
     RECT  0.108 26.779 0.234 27.115 ;
     RECT  11.844 26.933 11.862 27.131 ;
     RECT  17.46 27.095 19.854 27.131 ;
     RECT  21.636 26.923 22.23 27.131 ;
     RECT  14.256 27.095 16.542 27.167 ;
     RECT  4.392 26.933 11.07 27.203 ;
     RECT  14.256 27.167 15.39 27.203 ;
     RECT  22.176 27.131 22.23 27.203 ;
     RECT  0.108 27.115 0.342 27.211 ;
     RECT  9.54 27.203 11.07 27.211 ;
     RECT  22.212 27.203 22.23 27.239 ;
     RECT  14.256 27.203 14.85 27.329 ;
     RECT  16.2 27.167 16.542 27.329 ;
     RECT  17.928 27.131 19.854 27.329 ;
     RECT  14.256 27.329 14.274 27.365 ;
     RECT  17.964 27.329 19.422 27.365 ;
     RECT  20.88 27.175 20.898 27.365 ;
     RECT  18.432 27.365 18.897 27.389 ;
     RECT  13.176 26.933 13.497 27.599 ;
     RECT  0.108 27.211 0.558 27.644 ;
     RECT  9.54 27.211 11.25 27.707 ;
     RECT  9.54 27.707 9.558 27.743 ;
     RECT  10.332 27.707 11.25 27.743 ;
     RECT  13.215 27.599 13.497 27.827 ;
     RECT  18.615 27.389 18.897 27.827 ;
     RECT  2.415 26.933 3.51 27.841 ;
     RECT  4.392 27.203 8.622 27.841 ;
     RECT  10.8 27.743 11.25 27.905 ;
     RECT  2.415 27.841 8.622 27.941 ;
     RECT  2.415 27.941 3.51 28.097 ;
     RECT  5.22 27.941 8.622 28.097 ;
     RECT  13.215 27.827 13.305 28.097 ;
     RECT  18.615 27.827 18.705 28.097 ;
     RECT  0.144 27.644 0.558 28.109 ;
     RECT  5.22 28.097 7.398 28.205 ;
     RECT  5.22 28.205 6.858 28.301 ;
     RECT  0.54 28.109 0.558 28.493 ;
     RECT  8.604 28.097 8.622 28.493 ;
     RECT  2.736 28.097 3.51 28.685 ;
     RECT  3.492 28.685 3.51 28.781 ;
     RECT  5.22 28.301 6.57 28.877 ;
     RECT  5.58 28.877 6.57 28.973 ;
     RECT  2.736 28.685 2.754 29.069 ;
     RECT  1.404 26.599 1.422 29.165 ;
     RECT  5.58 28.973 6.246 29.261 ;
     RECT  5.58 29.261 5.598 29.357 ;
     RECT  11.232 27.905 11.25 29.453 ;
    LAYER M4 ;
     RECT  0.06 3.216 0.173 29.448 ;
     RECT  0.173 3.312 2.408 29.448 ;
     RECT  2.408 2.148 2.512 29.448 ;
     RECT  2.512 2.418 2.704 29.448 ;
     RECT  2.704 3.024 2.981 29.448 ;
     RECT  2.981 3.024 4.129 10.2 ;
     RECT  4.129 3.024 5.101 10.344 ;
     RECT  2.981 11.376 5.101 29.448 ;
     RECT  5.101 3.024 6.217 29.448 ;
     RECT  6.217 2.256 6.581 29.448 ;
     RECT  6.581 2.256 6.869 28.296 ;
     RECT  6.869 2.256 7.409 28.2 ;
     RECT  7.409 2.256 7.808 28.092 ;
     RECT  7.808 2.148 7.912 28.092 ;
     RECT  7.912 2.256 8.549 28.092 ;
     RECT  6.581 29.424 8.549 29.448 ;
     RECT  8.549 2.256 8.597 29.448 ;
     RECT  8.597 6 8.633 29.448 ;
     RECT  8.633 6 9.137 27.672 ;
     RECT  8.597 2.256 9.637 4.968 ;
     RECT  9.137 6 9.637 10.68 ;
     RECT  9.637 2.256 9.713 10.68 ;
     RECT  9.713 2.256 10.645 3.096 ;
     RECT  9.713 4.224 10.645 10.68 ;
     RECT  9.137 11.664 10.645 27.672 ;
     RECT  10.645 4.224 10.685 27.672 ;
     RECT  10.685 27.648 10.721 27.672 ;
     RECT  10.645 1.92 10.825 3.096 ;
     RECT  10.685 4.224 10.825 26.616 ;
     RECT  10.825 1.92 10.865 26.616 ;
     RECT  10.865 1.92 10.973 11.208 ;
     RECT  8.633 29.424 11.261 29.448 ;
     RECT  10.865 12.192 11.477 26.616 ;
     RECT  10.973 1.92 11.977 3.048 ;
     RECT  10.973 4.224 11.977 11.208 ;
     RECT  11.477 12.192 11.977 22.536 ;
     RECT  11.977 1.92 12.053 22.536 ;
     RECT  11.477 23.952 12.089 26.616 ;
     RECT  12.089 23.952 12.553 24.936 ;
     RECT  12.053 1.92 13.021 22.008 ;
     RECT  12.089 26.112 13.021 26.616 ;
     RECT  12.553 23.664 13.093 24.936 ;
     RECT  13.021 26.112 13.093 26.664 ;
     RECT  13.021 1.872 13.129 22.584 ;
     RECT  13.093 23.664 13.129 26.664 ;
     RECT  13.129 1.824 13.208 26.664 ;
     RECT  13.208 1.824 13.312 28.092 ;
     RECT  13.312 1.824 13.504 27.822 ;
     RECT  13.504 1.824 13.597 26.664 ;
     RECT  13.597 0.912 13.777 26.664 ;
     RECT  13.777 0.816 15.317 26.664 ;
     RECT  15.317 0.816 15.937 26.808 ;
     RECT  15.937 0.816 16.189 27.048 ;
     RECT  16.189 0.816 17.953 27.288 ;
     RECT  17.953 0.816 18.421 27.336 ;
     RECT  18.421 0.816 18.608 27.384 ;
     RECT  18.608 0.816 18.712 28.092 ;
     RECT  18.712 0.816 18.904 27.822 ;
     RECT  18.904 0.816 19.037 27.096 ;
     RECT  19.037 0.816 19.937 27 ;
     RECT  19.937 0.816 20.405 26.76 ;
     RECT  20.405 0.816 20.437 26.664 ;
     RECT  20.437 0.72 21.625 26.664 ;
     RECT  21.625 0.72 23.724 26.952 ;
    LAYER M5 ;
     RECT  2.4 2.137 2.52 2.151 ;
     RECT  7.8 2.137 7.92 2.151 ;
     RECT  13.2 2.137 13.32 2.151 ;
     RECT  18.6 2.137 18.72 2.151 ;
     RECT  13.2 2.151 13.512 2.773 ;
     RECT  2.4 2.151 2.712 3.013 ;
     RECT  17.136 2.245 17.16 3.443 ;
     RECT  15.264 1.861 15.288 3.635 ;
     RECT  13.2 2.773 13.608 3.685 ;
     RECT  0.144 3.589 0.168 3.779 ;
     RECT  13.2 3.685 15.144 3.875 ;
     RECT  17.04 4.261 17.064 4.451 ;
     RECT  20.112 4.117 20.136 4.499 ;
     RECT  18.6 2.151 18.912 4.597 ;
     RECT  18.288 4.597 18.912 4.883 ;
     RECT  2.4 3.013 3.48 5.509 ;
     RECT  17.184 5.317 17.208 5.605 ;
     RECT  1.68 5.509 3.48 5.651 ;
     RECT  6.432 5.557 6.456 5.747 ;
     RECT  16.944 5.605 17.208 5.893 ;
     RECT  16.752 5.893 17.208 6.037 ;
     RECT  16.752 6.037 17.256 6.227 ;
     RECT  16.752 6.227 16.968 6.277 ;
     RECT  16.656 6.277 16.968 6.467 ;
     RECT  15.12 3.875 15.144 6.515 ;
     RECT  13.2 3.875 13.512 7.765 ;
     RECT  16.944 6.467 16.968 9.157 ;
     RECT  16.56 9.157 16.968 9.203 ;
     RECT  16.56 9.203 16.584 9.205 ;
     RECT  14.784 10.213 14.808 10.835 ;
     RECT  13.008 7.765 13.512 10.883 ;
     RECT  16.368 9.205 16.584 11.219 ;
     RECT  7.8 2.151 8.112 11.221 ;
     RECT  7.68 11.221 8.112 11.411 ;
     RECT  14.832 11.365 14.856 11.507 ;
     RECT  0.24 12.229 0.264 12.371 ;
     RECT  14.928 12.517 14.952 12.707 ;
     RECT  16.368 11.219 16.392 12.997 ;
     RECT  2.4 5.651 3.48 13.189 ;
     RECT  2.4 13.189 3.912 13.379 ;
     RECT  7.8 11.411 8.112 14.389 ;
     RECT  6.912 14.389 8.112 14.531 ;
     RECT  2.4 13.379 3.48 14.581 ;
     RECT  15.888 12.997 16.392 14.627 ;
     RECT  7.8 14.531 8.112 14.677 ;
     RECT  2.4 14.581 4.008 14.771 ;
     RECT  15.888 14.627 16.104 14.915 ;
     RECT  13.2 10.883 13.512 15.493 ;
     RECT  14.544 15.589 14.568 16.259 ;
     RECT  17.088 16.261 17.112 16.403 ;
     RECT  20.4 16.261 20.424 16.403 ;
     RECT  16.08 14.915 16.104 16.405 ;
     RECT  0.576 17.989 0.6 18.131 ;
     RECT  12.96 15.493 13.512 18.227 ;
     RECT  16.08 16.405 16.536 18.851 ;
     RECT  14.64 18.565 14.664 19.237 ;
     RECT  16.176 18.851 16.536 19.475 ;
     RECT  14.496 19.237 14.664 19.811 ;
     RECT  14.496 19.811 14.52 20.339 ;
     RECT  13.2 18.227 13.512 21.061 ;
     RECT  0.144 21.733 0.168 22.019 ;
     RECT  13.2 21.061 13.704 22.883 ;
     RECT  16.512 19.475 16.536 25.715 ;
     RECT  0.144 25.765 0.168 26.051 ;
     RECT  2.4 14.771 3.48 26.243 ;
     RECT  15.36 26.149 15.384 26.819 ;
     RECT  9.648 26.581 9.672 27.395 ;
     RECT  2.4 26.243 2.712 28.089 ;
     RECT  13.2 22.883 13.512 28.089 ;
     RECT  18.6 4.883 18.912 28.089 ;
     RECT  2.4 28.089 2.52 28.103 ;
     RECT  7.8 14.677 8.52 28.103 ;
     RECT  13.2 28.089 13.32 28.103 ;
     RECT  18.6 28.089 18.72 28.103 ;
     RECT  8.496 28.103 8.52 28.453 ;
     RECT  8.496 28.453 8.616 30.224 ;
  END
END dsfd_rly_266_EW
END LIBRARY
